VERSION 5.8 ;
BUSBITCHARS "[]" ;
DIVIDERCHAR "/" ;
UNITS
    DATABASE MICRONS 1000 ;
END UNITS

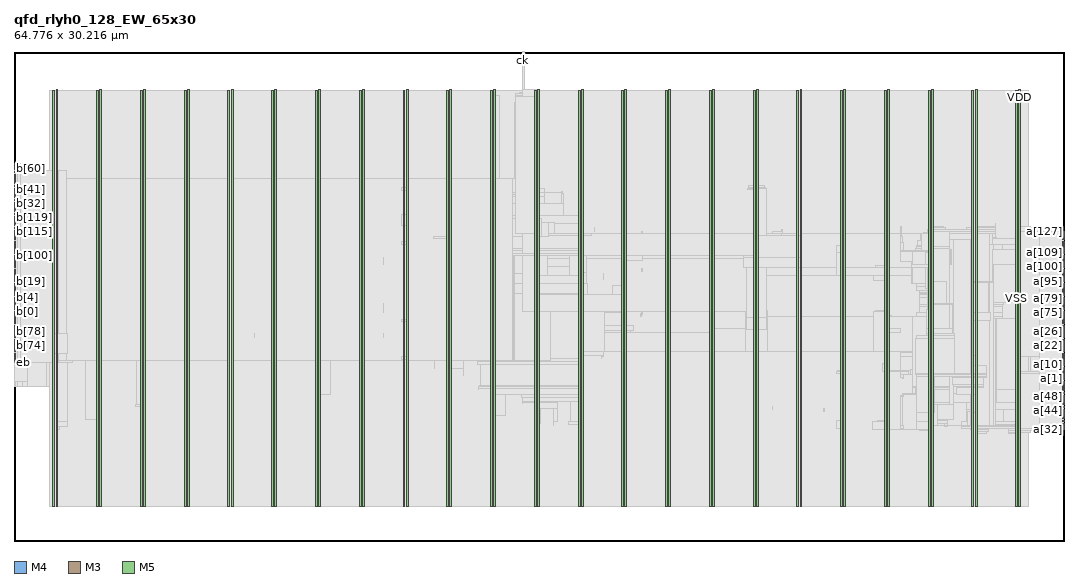
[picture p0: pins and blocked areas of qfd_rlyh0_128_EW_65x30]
MACRO qfd_rlyh0_128_EW_65x30
  FOREIGN qfd_rlyh0_128_EW_65x30 0 0 ;
  CLASS BLOCK ;
  SIZE 64.776 BY 30.216 ;
  PIN a[0]
    DIRECTION INPUT ;
    USE SIGNAL ;
    PORT
      LAYER M4 ;
        RECT  64.692 9.936 64.776 9.96 ;
    END
  END a[0]
  PIN a[100]
    DIRECTION INPUT ;
    USE SIGNAL ;
    PORT
      LAYER M4 ;
        RECT  64.692 16.464 64.776 16.488 ;
    END
  END a[100]
  PIN a[101]
    DIRECTION INPUT ;
    USE SIGNAL ;
    PORT
      LAYER M4 ;
        RECT  64.692 16.56 64.776 16.584 ;
    END
  END a[101]
  PIN a[102]
    DIRECTION INPUT ;
    USE SIGNAL ;
    PORT
      LAYER M4 ;
        RECT  64.692 16.656 64.776 16.68 ;
    END
  END a[102]
  PIN a[103]
    DIRECTION INPUT ;
    USE SIGNAL ;
    PORT
      LAYER M4 ;
        RECT  64.692 16.752 64.776 16.776 ;
    END
  END a[103]
  PIN a[104]
    DIRECTION INPUT ;
    USE SIGNAL ;
    PORT
      LAYER M4 ;
        RECT  64.692 16.848 64.776 16.872 ;
    END
  END a[104]
  PIN a[105]
    DIRECTION INPUT ;
    USE SIGNAL ;
    PORT
      LAYER M4 ;
        RECT  64.692 16.944 64.776 16.968 ;
    END
  END a[105]
  PIN a[106]
    DIRECTION INPUT ;
    USE SIGNAL ;
    PORT
      LAYER M4 ;
        RECT  64.692 17.04 64.776 17.064 ;
    END
  END a[106]
  PIN a[107]
    DIRECTION INPUT ;
    USE SIGNAL ;
    PORT
      LAYER M4 ;
        RECT  64.692 17.136 64.776 17.16 ;
    END
  END a[107]
  PIN a[108]
    DIRECTION INPUT ;
    USE SIGNAL ;
    PORT
      LAYER M4 ;
        RECT  64.692 17.232 64.776 17.256 ;
    END
  END a[108]
  PIN a[109]
    DIRECTION INPUT ;
    USE SIGNAL ;
    PORT
      LAYER M4 ;
        RECT  64.692 17.328 64.776 17.352 ;
    END
  END a[109]
  PIN a[10]
    DIRECTION INPUT ;
    USE SIGNAL ;
    PORT
      LAYER M4 ;
        RECT  64.692 10.896 64.776 10.92 ;
    END
  END a[10]
  PIN a[110]
    DIRECTION INPUT ;
    USE SIGNAL ;
    PORT
      LAYER M4 ;
        RECT  64.692 17.424 64.776 17.448 ;
    END
  END a[110]
  PIN a[111]
    DIRECTION INPUT ;
    USE SIGNAL ;
    PORT
      LAYER M4 ;
        RECT  64.692 17.52 64.776 17.544 ;
    END
  END a[111]
  PIN a[112]
    DIRECTION INPUT ;
    USE SIGNAL ;
    PORT
      LAYER M4 ;
        RECT  64.692 17.616 64.776 17.64 ;
    END
  END a[112]
  PIN a[113]
    DIRECTION INPUT ;
    USE SIGNAL ;
    PORT
      LAYER M4 ;
        RECT  64.692 17.712 64.776 17.736 ;
    END
  END a[113]
  PIN a[114]
    DIRECTION INPUT ;
    USE SIGNAL ;
    PORT
      LAYER M4 ;
        RECT  64.692 17.808 64.776 17.832 ;
    END
  END a[114]
  PIN a[115]
    DIRECTION INPUT ;
    USE SIGNAL ;
    PORT
      LAYER M4 ;
        RECT  64.692 17.904 64.776 17.928 ;
    END
  END a[115]
  PIN a[116]
    DIRECTION INPUT ;
    USE SIGNAL ;
    PORT
      LAYER M4 ;
        RECT  64.692 18 64.776 18.024 ;
    END
  END a[116]
  PIN a[117]
    DIRECTION INPUT ;
    USE SIGNAL ;
    PORT
      LAYER M4 ;
        RECT  64.692 18.096 64.776 18.12 ;
    END
  END a[117]
  PIN a[118]
    DIRECTION INPUT ;
    USE SIGNAL ;
    PORT
      LAYER M4 ;
        RECT  64.692 18.192 64.776 18.216 ;
    END
  END a[118]
  PIN a[119]
    DIRECTION INPUT ;
    USE SIGNAL ;
    PORT
      LAYER M4 ;
        RECT  64.692 18.288 64.776 18.312 ;
    END
  END a[119]
  PIN a[11]
    DIRECTION INPUT ;
    USE SIGNAL ;
    PORT
      LAYER M4 ;
        RECT  64.692 10.992 64.776 11.016 ;
    END
  END a[11]
  PIN a[120]
    DIRECTION INPUT ;
    USE SIGNAL ;
    PORT
      LAYER M4 ;
        RECT  64.692 18.384 64.776 18.408 ;
    END
  END a[120]
  PIN a[121]
    DIRECTION INPUT ;
    USE SIGNAL ;
    PORT
      LAYER M4 ;
        RECT  64.692 18.48 64.776 18.504 ;
    END
  END a[121]
  PIN a[122]
    DIRECTION INPUT ;
    USE SIGNAL ;
    PORT
      LAYER M4 ;
        RECT  64.692 18.576 64.776 18.6 ;
    END
  END a[122]
  PIN a[123]
    DIRECTION INPUT ;
    USE SIGNAL ;
    PORT
      LAYER M4 ;
        RECT  64.692 18.672 64.776 18.696 ;
    END
  END a[123]
  PIN a[124]
    DIRECTION INPUT ;
    USE SIGNAL ;
    PORT
      LAYER M4 ;
        RECT  64.692 18.768 64.776 18.792 ;
    END
  END a[124]
  PIN a[125]
    DIRECTION INPUT ;
    USE SIGNAL ;
    PORT
      LAYER M4 ;
        RECT  64.692 18.864 64.776 18.888 ;
    END
  END a[125]
  PIN a[126]
    DIRECTION INPUT ;
    USE SIGNAL ;
    PORT
      LAYER M4 ;
        RECT  64.692 18.96 64.776 18.984 ;
    END
  END a[126]
  PIN a[127]
    DIRECTION INPUT ;
    USE SIGNAL ;
    PORT
      LAYER M4 ;
        RECT  64.692 19.056 64.776 19.08 ;
    END
  END a[127]
  PIN a[12]
    DIRECTION INPUT ;
    USE SIGNAL ;
    PORT
      LAYER M4 ;
        RECT  64.692 11.088 64.776 11.112 ;
    END
  END a[12]
  PIN a[13]
    DIRECTION INPUT ;
    USE SIGNAL ;
    PORT
      LAYER M4 ;
        RECT  64.692 11.184 64.776 11.208 ;
    END
  END a[13]
  PIN a[14]
    DIRECTION INPUT ;
    USE SIGNAL ;
    PORT
      LAYER M4 ;
        RECT  64.692 11.28 64.776 11.304 ;
    END
  END a[14]
  PIN a[15]
    DIRECTION INPUT ;
    USE SIGNAL ;
    PORT
      LAYER M4 ;
        RECT  64.692 11.376 64.776 11.4 ;
    END
  END a[15]
  PIN a[16]
    DIRECTION INPUT ;
    USE SIGNAL ;
    PORT
      LAYER M4 ;
        RECT  64.692 11.472 64.776 11.496 ;
    END
  END a[16]
  PIN a[17]
    DIRECTION INPUT ;
    USE SIGNAL ;
    PORT
      LAYER M4 ;
        RECT  64.692 11.568 64.776 11.592 ;
    END
  END a[17]
  PIN a[18]
    DIRECTION INPUT ;
    USE SIGNAL ;
    PORT
      LAYER M4 ;
        RECT  64.692 11.664 64.776 11.688 ;
    END
  END a[18]
  PIN a[19]
    DIRECTION INPUT ;
    USE SIGNAL ;
    PORT
      LAYER M4 ;
        RECT  64.692 11.76 64.776 11.784 ;
    END
  END a[19]
  PIN a[1]
    DIRECTION INPUT ;
    USE SIGNAL ;
    PORT
      LAYER M4 ;
        RECT  64.692 10.032 64.776 10.056 ;
    END
  END a[1]
  PIN a[20]
    DIRECTION INPUT ;
    USE SIGNAL ;
    PORT
      LAYER M4 ;
        RECT  64.692 11.856 64.776 11.88 ;
    END
  END a[20]
  PIN a[21]
    DIRECTION INPUT ;
    USE SIGNAL ;
    PORT
      LAYER M4 ;
        RECT  64.692 11.952 64.776 11.976 ;
    END
  END a[21]
  PIN a[22]
    DIRECTION INPUT ;
    USE SIGNAL ;
    PORT
      LAYER M4 ;
        RECT  64.692 12.048 64.776 12.072 ;
    END
  END a[22]
  PIN a[23]
    DIRECTION INPUT ;
    USE SIGNAL ;
    PORT
      LAYER M4 ;
        RECT  64.692 12.144 64.776 12.168 ;
    END
  END a[23]
  PIN a[24]
    DIRECTION INPUT ;
    USE SIGNAL ;
    PORT
      LAYER M4 ;
        RECT  64.692 12.24 64.776 12.264 ;
    END
  END a[24]
  PIN a[25]
    DIRECTION INPUT ;
    USE SIGNAL ;
    PORT
      LAYER M4 ;
        RECT  64.692 12.336 64.776 12.36 ;
    END
  END a[25]
  PIN a[26]
    DIRECTION INPUT ;
    USE SIGNAL ;
    PORT
      LAYER M4 ;
        RECT  64.692 12.432 64.776 12.456 ;
    END
  END a[26]
  PIN a[27]
    DIRECTION INPUT ;
    USE SIGNAL ;
    PORT
      LAYER M4 ;
        RECT  64.692 12.528 64.776 12.552 ;
    END
  END a[27]
  PIN a[28]
    DIRECTION INPUT ;
    USE SIGNAL ;
    PORT
      LAYER M4 ;
        RECT  64.692 12.624 64.776 12.648 ;
    END
  END a[28]
  PIN a[29]
    DIRECTION INPUT ;
    USE SIGNAL ;
    PORT
      LAYER M4 ;
        RECT  64.692 12.72 64.776 12.744 ;
    END
  END a[29]
  PIN a[2]
    DIRECTION INPUT ;
    USE SIGNAL ;
    PORT
      LAYER M4 ;
        RECT  64.692 10.128 64.776 10.152 ;
    END
  END a[2]
  PIN a[30]
    DIRECTION INPUT ;
    USE SIGNAL ;
    PORT
      LAYER M4 ;
        RECT  64.692 12.816 64.776 12.84 ;
    END
  END a[30]
  PIN a[31]
    DIRECTION INPUT ;
    USE SIGNAL ;
    PORT
      LAYER M4 ;
        RECT  64.692 12.912 64.776 12.936 ;
    END
  END a[31]
  PIN a[32]
    DIRECTION INPUT ;
    USE SIGNAL ;
    PORT
      LAYER M4 ;
        RECT  64.692 6.864 64.776 6.888 ;
    END
  END a[32]
  PIN a[33]
    DIRECTION INPUT ;
    USE SIGNAL ;
    PORT
      LAYER M4 ;
        RECT  64.692 6.96 64.776 6.984 ;
    END
  END a[33]
  PIN a[34]
    DIRECTION INPUT ;
    USE SIGNAL ;
    PORT
      LAYER M4 ;
        RECT  64.692 7.056 64.776 7.08 ;
    END
  END a[34]
  PIN a[35]
    DIRECTION INPUT ;
    USE SIGNAL ;
    PORT
      LAYER M4 ;
        RECT  64.692 7.152 64.776 7.176 ;
    END
  END a[35]
  PIN a[36]
    DIRECTION INPUT ;
    USE SIGNAL ;
    PORT
      LAYER M4 ;
        RECT  64.692 7.248 64.776 7.272 ;
    END
  END a[36]
  PIN a[37]
    DIRECTION INPUT ;
    USE SIGNAL ;
    PORT
      LAYER M4 ;
        RECT  64.692 7.344 64.776 7.368 ;
    END
  END a[37]
  PIN a[38]
    DIRECTION INPUT ;
    USE SIGNAL ;
    PORT
      LAYER M4 ;
        RECT  64.692 7.44 64.776 7.464 ;
    END
  END a[38]
  PIN a[39]
    DIRECTION INPUT ;
    USE SIGNAL ;
    PORT
      LAYER M4 ;
        RECT  64.692 7.536 64.776 7.56 ;
    END
  END a[39]
  PIN a[3]
    DIRECTION INPUT ;
    USE SIGNAL ;
    PORT
      LAYER M4 ;
        RECT  64.692 10.224 64.776 10.248 ;
    END
  END a[3]
  PIN a[40]
    DIRECTION INPUT ;
    USE SIGNAL ;
    PORT
      LAYER M4 ;
        RECT  64.692 7.632 64.776 7.656 ;
    END
  END a[40]
  PIN a[41]
    DIRECTION INPUT ;
    USE SIGNAL ;
    PORT
      LAYER M4 ;
        RECT  64.692 7.728 64.776 7.752 ;
    END
  END a[41]
  PIN a[42]
    DIRECTION INPUT ;
    USE SIGNAL ;
    PORT
      LAYER M4 ;
        RECT  64.692 7.824 64.776 7.848 ;
    END
  END a[42]
  PIN a[43]
    DIRECTION INPUT ;
    USE SIGNAL ;
    PORT
      LAYER M4 ;
        RECT  64.692 7.92 64.776 7.944 ;
    END
  END a[43]
  PIN a[44]
    DIRECTION INPUT ;
    USE SIGNAL ;
    PORT
      LAYER M4 ;
        RECT  64.692 8.016 64.776 8.04 ;
    END
  END a[44]
  PIN a[45]
    DIRECTION INPUT ;
    USE SIGNAL ;
    PORT
      LAYER M4 ;
        RECT  64.692 8.112 64.776 8.136 ;
    END
  END a[45]
  PIN a[46]
    DIRECTION INPUT ;
    USE SIGNAL ;
    PORT
      LAYER M4 ;
        RECT  64.692 8.208 64.776 8.232 ;
    END
  END a[46]
  PIN a[47]
    DIRECTION INPUT ;
    USE SIGNAL ;
    PORT
      LAYER M4 ;
        RECT  64.692 8.304 64.776 8.328 ;
    END
  END a[47]
  PIN a[48]
    DIRECTION INPUT ;
    USE SIGNAL ;
    PORT
      LAYER M4 ;
        RECT  64.692 8.4 64.776 8.424 ;
    END
  END a[48]
  PIN a[49]
    DIRECTION INPUT ;
    USE SIGNAL ;
    PORT
      LAYER M4 ;
        RECT  64.692 8.496 64.776 8.52 ;
    END
  END a[49]
  PIN a[4]
    DIRECTION INPUT ;
    USE SIGNAL ;
    PORT
      LAYER M4 ;
        RECT  64.692 10.32 64.776 10.344 ;
    END
  END a[4]
  PIN a[50]
    DIRECTION INPUT ;
    USE SIGNAL ;
    PORT
      LAYER M4 ;
        RECT  64.692 8.592 64.776 8.616 ;
    END
  END a[50]
  PIN a[51]
    DIRECTION INPUT ;
    USE SIGNAL ;
    PORT
      LAYER M4 ;
        RECT  64.692 8.688 64.776 8.712 ;
    END
  END a[51]
  PIN a[52]
    DIRECTION INPUT ;
    USE SIGNAL ;
    PORT
      LAYER M4 ;
        RECT  64.692 8.784 64.776 8.808 ;
    END
  END a[52]
  PIN a[53]
    DIRECTION INPUT ;
    USE SIGNAL ;
    PORT
      LAYER M4 ;
        RECT  64.692 8.88 64.776 8.904 ;
    END
  END a[53]
  PIN a[54]
    DIRECTION INPUT ;
    USE SIGNAL ;
    PORT
      LAYER M4 ;
        RECT  64.692 8.976 64.776 9 ;
    END
  END a[54]
  PIN a[55]
    DIRECTION INPUT ;
    USE SIGNAL ;
    PORT
      LAYER M4 ;
        RECT  64.692 9.072 64.776 9.096 ;
    END
  END a[55]
  PIN a[56]
    DIRECTION INPUT ;
    USE SIGNAL ;
    PORT
      LAYER M4 ;
        RECT  64.692 9.168 64.776 9.192 ;
    END
  END a[56]
  PIN a[57]
    DIRECTION INPUT ;
    USE SIGNAL ;
    PORT
      LAYER M4 ;
        RECT  64.692 9.264 64.776 9.288 ;
    END
  END a[57]
  PIN a[58]
    DIRECTION INPUT ;
    USE SIGNAL ;
    PORT
      LAYER M4 ;
        RECT  64.692 9.36 64.776 9.384 ;
    END
  END a[58]
  PIN a[59]
    DIRECTION INPUT ;
    USE SIGNAL ;
    PORT
      LAYER M4 ;
        RECT  64.692 9.456 64.776 9.48 ;
    END
  END a[59]
  PIN a[5]
    DIRECTION INPUT ;
    USE SIGNAL ;
    PORT
      LAYER M4 ;
        RECT  64.692 10.416 64.776 10.44 ;
    END
  END a[5]
  PIN a[60]
    DIRECTION INPUT ;
    USE SIGNAL ;
    PORT
      LAYER M4 ;
        RECT  64.692 9.552 64.776 9.576 ;
    END
  END a[60]
  PIN a[61]
    DIRECTION INPUT ;
    USE SIGNAL ;
    PORT
      LAYER M4 ;
        RECT  64.692 9.648 64.776 9.672 ;
    END
  END a[61]
  PIN a[62]
    DIRECTION INPUT ;
    USE SIGNAL ;
    PORT
      LAYER M4 ;
        RECT  64.692 9.744 64.776 9.768 ;
    END
  END a[62]
  PIN a[63]
    DIRECTION INPUT ;
    USE SIGNAL ;
    PORT
      LAYER M4 ;
        RECT  64.692 9.84 64.776 9.864 ;
    END
  END a[63]
  PIN a[64]
    DIRECTION INPUT ;
    USE SIGNAL ;
    PORT
      LAYER M4 ;
        RECT  64.692 13.008 64.776 13.032 ;
    END
  END a[64]
  PIN a[65]
    DIRECTION INPUT ;
    USE SIGNAL ;
    PORT
      LAYER M4 ;
        RECT  64.692 13.104 64.776 13.128 ;
    END
  END a[65]
  PIN a[66]
    DIRECTION INPUT ;
    USE SIGNAL ;
    PORT
      LAYER M4 ;
        RECT  64.692 13.2 64.776 13.224 ;
    END
  END a[66]
  PIN a[67]
    DIRECTION INPUT ;
    USE SIGNAL ;
    PORT
      LAYER M4 ;
        RECT  64.692 13.296 64.776 13.32 ;
    END
  END a[67]
  PIN a[68]
    DIRECTION INPUT ;
    USE SIGNAL ;
    PORT
      LAYER M4 ;
        RECT  64.692 13.392 64.776 13.416 ;
    END
  END a[68]
  PIN a[69]
    DIRECTION INPUT ;
    USE SIGNAL ;
    PORT
      LAYER M4 ;
        RECT  64.692 13.488 64.776 13.512 ;
    END
  END a[69]
  PIN a[6]
    DIRECTION INPUT ;
    USE SIGNAL ;
    PORT
      LAYER M4 ;
        RECT  64.692 10.512 64.776 10.536 ;
    END
  END a[6]
  PIN a[70]
    DIRECTION INPUT ;
    USE SIGNAL ;
    PORT
      LAYER M4 ;
        RECT  64.692 13.584 64.776 13.608 ;
    END
  END a[70]
  PIN a[71]
    DIRECTION INPUT ;
    USE SIGNAL ;
    PORT
      LAYER M4 ;
        RECT  64.692 13.68 64.776 13.704 ;
    END
  END a[71]
  PIN a[72]
    DIRECTION INPUT ;
    USE SIGNAL ;
    PORT
      LAYER M4 ;
        RECT  64.692 13.776 64.776 13.8 ;
    END
  END a[72]
  PIN a[73]
    DIRECTION INPUT ;
    USE SIGNAL ;
    PORT
      LAYER M4 ;
        RECT  64.692 13.872 64.776 13.896 ;
    END
  END a[73]
  PIN a[74]
    DIRECTION INPUT ;
    USE SIGNAL ;
    PORT
      LAYER M4 ;
        RECT  64.692 13.968 64.776 13.992 ;
    END
  END a[74]
  PIN a[75]
    DIRECTION INPUT ;
    USE SIGNAL ;
    PORT
      LAYER M4 ;
        RECT  64.692 14.064 64.776 14.088 ;
    END
  END a[75]
  PIN a[76]
    DIRECTION INPUT ;
    USE SIGNAL ;
    PORT
      LAYER M4 ;
        RECT  64.692 14.16 64.776 14.184 ;
    END
  END a[76]
  PIN a[77]
    DIRECTION INPUT ;
    USE SIGNAL ;
    PORT
      LAYER M4 ;
        RECT  64.692 14.256 64.776 14.28 ;
    END
  END a[77]
  PIN a[78]
    DIRECTION INPUT ;
    USE SIGNAL ;
    PORT
      LAYER M4 ;
        RECT  64.692 14.352 64.776 14.376 ;
    END
  END a[78]
  PIN a[79]
    DIRECTION INPUT ;
    USE SIGNAL ;
    PORT
      LAYER M4 ;
        RECT  64.692 14.448 64.776 14.472 ;
    END
  END a[79]
  PIN a[7]
    DIRECTION INPUT ;
    USE SIGNAL ;
    PORT
      LAYER M4 ;
        RECT  64.692 10.608 64.776 10.632 ;
    END
  END a[7]
  PIN a[80]
    DIRECTION INPUT ;
    USE SIGNAL ;
    PORT
      LAYER M4 ;
        RECT  64.692 14.544 64.776 14.568 ;
    END
  END a[80]
  PIN a[81]
    DIRECTION INPUT ;
    USE SIGNAL ;
    PORT
      LAYER M4 ;
        RECT  64.692 14.64 64.776 14.664 ;
    END
  END a[81]
  PIN a[82]
    DIRECTION INPUT ;
    USE SIGNAL ;
    PORT
      LAYER M4 ;
        RECT  64.692 14.736 64.776 14.76 ;
    END
  END a[82]
  PIN a[83]
    DIRECTION INPUT ;
    USE SIGNAL ;
    PORT
      LAYER M4 ;
        RECT  64.692 14.832 64.776 14.856 ;
    END
  END a[83]
  PIN a[84]
    DIRECTION INPUT ;
    USE SIGNAL ;
    PORT
      LAYER M4 ;
        RECT  64.692 14.928 64.776 14.952 ;
    END
  END a[84]
  PIN a[85]
    DIRECTION INPUT ;
    USE SIGNAL ;
    PORT
      LAYER M4 ;
        RECT  64.692 15.024 64.776 15.048 ;
    END
  END a[85]
  PIN a[86]
    DIRECTION INPUT ;
    USE SIGNAL ;
    PORT
      LAYER M4 ;
        RECT  64.692 15.12 64.776 15.144 ;
    END
  END a[86]
  PIN a[87]
    DIRECTION INPUT ;
    USE SIGNAL ;
    PORT
      LAYER M4 ;
        RECT  64.692 15.216 64.776 15.24 ;
    END
  END a[87]
  PIN a[88]
    DIRECTION INPUT ;
    USE SIGNAL ;
    PORT
      LAYER M4 ;
        RECT  64.692 15.312 64.776 15.336 ;
    END
  END a[88]
  PIN a[89]
    DIRECTION INPUT ;
    USE SIGNAL ;
    PORT
      LAYER M4 ;
        RECT  64.692 15.408 64.776 15.432 ;
    END
  END a[89]
  PIN a[8]
    DIRECTION INPUT ;
    USE SIGNAL ;
    PORT
      LAYER M4 ;
        RECT  64.692 10.704 64.776 10.728 ;
    END
  END a[8]
  PIN a[90]
    DIRECTION INPUT ;
    USE SIGNAL ;
    PORT
      LAYER M4 ;
        RECT  64.692 15.504 64.776 15.528 ;
    END
  END a[90]
  PIN a[91]
    DIRECTION INPUT ;
    USE SIGNAL ;
    PORT
      LAYER M4 ;
        RECT  64.692 15.6 64.776 15.624 ;
    END
  END a[91]
  PIN a[92]
    DIRECTION INPUT ;
    USE SIGNAL ;
    PORT
      LAYER M4 ;
        RECT  64.692 15.696 64.776 15.72 ;
    END
  END a[92]
  PIN a[93]
    DIRECTION INPUT ;
    USE SIGNAL ;
    PORT
      LAYER M4 ;
        RECT  64.692 15.792 64.776 15.816 ;
    END
  END a[93]
  PIN a[94]
    DIRECTION INPUT ;
    USE SIGNAL ;
    PORT
      LAYER M4 ;
        RECT  64.692 15.888 64.776 15.912 ;
    END
  END a[94]
  PIN a[95]
    DIRECTION INPUT ;
    USE SIGNAL ;
    PORT
      LAYER M4 ;
        RECT  64.692 15.984 64.776 16.008 ;
    END
  END a[95]
  PIN a[96]
    DIRECTION INPUT ;
    USE SIGNAL ;
    PORT
      LAYER M4 ;
        RECT  64.692 16.08 64.776 16.104 ;
    END
  END a[96]
  PIN a[97]
    DIRECTION INPUT ;
    USE SIGNAL ;
    PORT
      LAYER M4 ;
        RECT  64.692 16.176 64.776 16.2 ;
    END
  END a[97]
  PIN a[98]
    DIRECTION INPUT ;
    USE SIGNAL ;
    PORT
      LAYER M4 ;
        RECT  64.692 16.272 64.776 16.296 ;
    END
  END a[98]
  PIN a[99]
    DIRECTION INPUT ;
    USE SIGNAL ;
    PORT
      LAYER M4 ;
        RECT  64.692 16.368 64.776 16.392 ;
    END
  END a[99]
  PIN a[9]
    DIRECTION INPUT ;
    USE SIGNAL ;
    PORT
      LAYER M4 ;
        RECT  64.692 10.8 64.776 10.824 ;
    END
  END a[9]
  PIN b[0]
    DIRECTION OUTPUT ;
    USE SIGNAL ;
    PORT
      LAYER M4 ;
        RECT  0 14.16 0.084 14.184 ;
    END
  END b[0]
  PIN b[100]
    DIRECTION OUTPUT ;
    USE SIGNAL ;
    PORT
      LAYER M4 ;
        RECT  0 17.616 0.084 17.64 ;
    END
  END b[100]
  PIN b[101]
    DIRECTION OUTPUT ;
    USE SIGNAL ;
    PORT
      LAYER M4 ;
        RECT  0 17.712 0.084 17.736 ;
    END
  END b[101]
  PIN b[102]
    DIRECTION OUTPUT ;
    USE SIGNAL ;
    PORT
      LAYER M4 ;
        RECT  0 17.808 0.084 17.832 ;
    END
  END b[102]
  PIN b[103]
    DIRECTION OUTPUT ;
    USE SIGNAL ;
    PORT
      LAYER M4 ;
        RECT  0 17.904 0.084 17.928 ;
    END
  END b[103]
  PIN b[104]
    DIRECTION OUTPUT ;
    USE SIGNAL ;
    PORT
      LAYER M4 ;
        RECT  0 18 0.084 18.024 ;
    END
  END b[104]
  PIN b[105]
    DIRECTION OUTPUT ;
    USE SIGNAL ;
    PORT
      LAYER M4 ;
        RECT  0 18.096 0.084 18.12 ;
    END
  END b[105]
  PIN b[106]
    DIRECTION OUTPUT ;
    USE SIGNAL ;
    PORT
      LAYER M4 ;
        RECT  0 18.192 0.084 18.216 ;
    END
  END b[106]
  PIN b[107]
    DIRECTION OUTPUT ;
    USE SIGNAL ;
    PORT
      LAYER M4 ;
        RECT  0 18.288 0.084 18.312 ;
    END
  END b[107]
  PIN b[108]
    DIRECTION OUTPUT ;
    USE SIGNAL ;
    PORT
      LAYER M4 ;
        RECT  0 18.384 0.084 18.408 ;
    END
  END b[108]
  PIN b[109]
    DIRECTION OUTPUT ;
    USE SIGNAL ;
    PORT
      LAYER M4 ;
        RECT  0 18.48 0.084 18.504 ;
    END
  END b[109]
  PIN b[10]
    DIRECTION OUTPUT ;
    USE SIGNAL ;
    PORT
      LAYER M4 ;
        RECT  0 15.12 0.084 15.144 ;
    END
  END b[10]
  PIN b[110]
    DIRECTION OUTPUT ;
    USE SIGNAL ;
    PORT
      LAYER M4 ;
        RECT  0 18.576 0.084 18.6 ;
    END
  END b[110]
  PIN b[111]
    DIRECTION OUTPUT ;
    USE SIGNAL ;
    PORT
      LAYER M4 ;
        RECT  0 18.672 0.084 18.696 ;
    END
  END b[111]
  PIN b[112]
    DIRECTION OUTPUT ;
    USE SIGNAL ;
    PORT
      LAYER M4 ;
        RECT  0 18.768 0.084 18.792 ;
    END
  END b[112]
  PIN b[113]
    DIRECTION OUTPUT ;
    USE SIGNAL ;
    PORT
      LAYER M4 ;
        RECT  0 18.864 0.084 18.888 ;
    END
  END b[113]
  PIN b[114]
    DIRECTION OUTPUT ;
    USE SIGNAL ;
    PORT
      LAYER M4 ;
        RECT  0 18.96 0.084 18.984 ;
    END
  END b[114]
  PIN b[115]
    DIRECTION OUTPUT ;
    USE SIGNAL ;
    PORT
      LAYER M4 ;
        RECT  0 19.056 0.084 19.08 ;
    END
  END b[115]
  PIN b[116]
    DIRECTION OUTPUT ;
    USE SIGNAL ;
    PORT
      LAYER M4 ;
        RECT  0 19.152 0.084 19.176 ;
    END
  END b[116]
  PIN b[117]
    DIRECTION OUTPUT ;
    USE SIGNAL ;
    PORT
      LAYER M4 ;
        RECT  0 19.248 0.084 19.272 ;
    END
  END b[117]
  PIN b[118]
    DIRECTION OUTPUT ;
    USE SIGNAL ;
    PORT
      LAYER M4 ;
        RECT  0 19.344 0.084 19.368 ;
    END
  END b[118]
  PIN b[119]
    DIRECTION OUTPUT ;
    USE SIGNAL ;
    PORT
      LAYER M4 ;
        RECT  0 19.44 0.084 19.464 ;
    END
  END b[119]
  PIN b[11]
    DIRECTION OUTPUT ;
    USE SIGNAL ;
    PORT
      LAYER M4 ;
        RECT  0 15.216 0.084 15.24 ;
    END
  END b[11]
  PIN b[120]
    DIRECTION OUTPUT ;
    USE SIGNAL ;
    PORT
      LAYER M4 ;
        RECT  0 19.536 0.084 19.56 ;
    END
  END b[120]
  PIN b[121]
    DIRECTION OUTPUT ;
    USE SIGNAL ;
    PORT
      LAYER M4 ;
        RECT  0 19.632 0.084 19.656 ;
    END
  END b[121]
  PIN b[122]
    DIRECTION OUTPUT ;
    USE SIGNAL ;
    PORT
      LAYER M4 ;
        RECT  0 19.728 0.084 19.752 ;
    END
  END b[122]
  PIN b[123]
    DIRECTION OUTPUT ;
    USE SIGNAL ;
    PORT
      LAYER M4 ;
        RECT  0 19.824 0.084 19.848 ;
    END
  END b[123]
  PIN b[124]
    DIRECTION OUTPUT ;
    USE SIGNAL ;
    PORT
      LAYER M4 ;
        RECT  0 19.92 0.084 19.944 ;
    END
  END b[124]
  PIN b[125]
    DIRECTION OUTPUT ;
    USE SIGNAL ;
    PORT
      LAYER M4 ;
        RECT  0 20.016 0.084 20.04 ;
    END
  END b[125]
  PIN b[126]
    DIRECTION OUTPUT ;
    USE SIGNAL ;
    PORT
      LAYER M4 ;
        RECT  0 20.112 0.084 20.136 ;
    END
  END b[126]
  PIN b[127]
    DIRECTION OUTPUT ;
    USE SIGNAL ;
    PORT
      LAYER M4 ;
        RECT  0 20.208 0.084 20.232 ;
    END
  END b[127]
  PIN b[12]
    DIRECTION OUTPUT ;
    USE SIGNAL ;
    PORT
      LAYER M4 ;
        RECT  0 15.312 0.084 15.336 ;
    END
  END b[12]
  PIN b[13]
    DIRECTION OUTPUT ;
    USE SIGNAL ;
    PORT
      LAYER M4 ;
        RECT  0 15.408 0.084 15.432 ;
    END
  END b[13]
  PIN b[14]
    DIRECTION OUTPUT ;
    USE SIGNAL ;
    PORT
      LAYER M4 ;
        RECT  0 15.504 0.084 15.528 ;
    END
  END b[14]
  PIN b[15]
    DIRECTION OUTPUT ;
    USE SIGNAL ;
    PORT
      LAYER M4 ;
        RECT  0 15.6 0.084 15.624 ;
    END
  END b[15]
  PIN b[16]
    DIRECTION OUTPUT ;
    USE SIGNAL ;
    PORT
      LAYER M4 ;
        RECT  0 15.696 0.084 15.72 ;
    END
  END b[16]
  PIN b[17]
    DIRECTION OUTPUT ;
    USE SIGNAL ;
    PORT
      LAYER M4 ;
        RECT  0 15.792 0.084 15.816 ;
    END
  END b[17]
  PIN b[18]
    DIRECTION OUTPUT ;
    USE SIGNAL ;
    PORT
      LAYER M4 ;
        RECT  0 15.888 0.084 15.912 ;
    END
  END b[18]
  PIN b[19]
    DIRECTION OUTPUT ;
    USE SIGNAL ;
    PORT
      LAYER M4 ;
        RECT  0 15.984 0.084 16.008 ;
    END
  END b[19]
  PIN b[1]
    DIRECTION OUTPUT ;
    USE SIGNAL ;
    PORT
      LAYER M4 ;
        RECT  0 14.256 0.084 14.28 ;
    END
  END b[1]
  PIN b[20]
    DIRECTION OUTPUT ;
    USE SIGNAL ;
    PORT
      LAYER M4 ;
        RECT  0 16.08 0.084 16.104 ;
    END
  END b[20]
  PIN b[21]
    DIRECTION OUTPUT ;
    USE SIGNAL ;
    PORT
      LAYER M4 ;
        RECT  0 16.176 0.084 16.2 ;
    END
  END b[21]
  PIN b[22]
    DIRECTION OUTPUT ;
    USE SIGNAL ;
    PORT
      LAYER M4 ;
        RECT  0 16.272 0.084 16.296 ;
    END
  END b[22]
  PIN b[23]
    DIRECTION OUTPUT ;
    USE SIGNAL ;
    PORT
      LAYER M4 ;
        RECT  0 16.368 0.084 16.392 ;
    END
  END b[23]
  PIN b[24]
    DIRECTION OUTPUT ;
    USE SIGNAL ;
    PORT
      LAYER M4 ;
        RECT  0 16.464 0.084 16.488 ;
    END
  END b[24]
  PIN b[25]
    DIRECTION OUTPUT ;
    USE SIGNAL ;
    PORT
      LAYER M4 ;
        RECT  0 16.56 0.084 16.584 ;
    END
  END b[25]
  PIN b[26]
    DIRECTION OUTPUT ;
    USE SIGNAL ;
    PORT
      LAYER M4 ;
        RECT  0 16.656 0.084 16.68 ;
    END
  END b[26]
  PIN b[27]
    DIRECTION OUTPUT ;
    USE SIGNAL ;
    PORT
      LAYER M4 ;
        RECT  0 16.752 0.084 16.776 ;
    END
  END b[27]
  PIN b[28]
    DIRECTION OUTPUT ;
    USE SIGNAL ;
    PORT
      LAYER M4 ;
        RECT  0 16.848 0.084 16.872 ;
    END
  END b[28]
  PIN b[29]
    DIRECTION OUTPUT ;
    USE SIGNAL ;
    PORT
      LAYER M4 ;
        RECT  0 16.944 0.084 16.968 ;
    END
  END b[29]
  PIN b[2]
    DIRECTION OUTPUT ;
    USE SIGNAL ;
    PORT
      LAYER M4 ;
        RECT  0 14.352 0.084 14.376 ;
    END
  END b[2]
  PIN b[30]
    DIRECTION OUTPUT ;
    USE SIGNAL ;
    PORT
      LAYER M4 ;
        RECT  0 17.04 0.084 17.064 ;
    END
  END b[30]
  PIN b[31]
    DIRECTION OUTPUT ;
    USE SIGNAL ;
    PORT
      LAYER M4 ;
        RECT  0 17.136 0.084 17.16 ;
    END
  END b[31]
  PIN b[32]
    DIRECTION OUTPUT ;
    USE SIGNAL ;
    PORT
      LAYER M4 ;
        RECT  0 20.304 0.084 20.328 ;
    END
  END b[32]
  PIN b[33]
    DIRECTION OUTPUT ;
    USE SIGNAL ;
    PORT
      LAYER M4 ;
        RECT  0 20.4 0.084 20.424 ;
    END
  END b[33]
  PIN b[34]
    DIRECTION OUTPUT ;
    USE SIGNAL ;
    PORT
      LAYER M4 ;
        RECT  0 20.496 0.084 20.52 ;
    END
  END b[34]
  PIN b[35]
    DIRECTION OUTPUT ;
    USE SIGNAL ;
    PORT
      LAYER M4 ;
        RECT  0 20.592 0.084 20.616 ;
    END
  END b[35]
  PIN b[36]
    DIRECTION OUTPUT ;
    USE SIGNAL ;
    PORT
      LAYER M4 ;
        RECT  0 20.688 0.084 20.712 ;
    END
  END b[36]
  PIN b[37]
    DIRECTION OUTPUT ;
    USE SIGNAL ;
    PORT
      LAYER M4 ;
        RECT  0 20.784 0.084 20.808 ;
    END
  END b[37]
  PIN b[38]
    DIRECTION OUTPUT ;
    USE SIGNAL ;
    PORT
      LAYER M4 ;
        RECT  0 20.88 0.084 20.904 ;
    END
  END b[38]
  PIN b[39]
    DIRECTION OUTPUT ;
    USE SIGNAL ;
    PORT
      LAYER M4 ;
        RECT  0 20.976 0.084 21 ;
    END
  END b[39]
  PIN b[3]
    DIRECTION OUTPUT ;
    USE SIGNAL ;
    PORT
      LAYER M4 ;
        RECT  0 14.448 0.084 14.472 ;
    END
  END b[3]
  PIN b[40]
    DIRECTION OUTPUT ;
    USE SIGNAL ;
    PORT
      LAYER M4 ;
        RECT  0 21.072 0.084 21.096 ;
    END
  END b[40]
  PIN b[41]
    DIRECTION OUTPUT ;
    USE SIGNAL ;
    PORT
      LAYER M4 ;
        RECT  0 21.168 0.084 21.192 ;
    END
  END b[41]
  PIN b[42]
    DIRECTION OUTPUT ;
    USE SIGNAL ;
    PORT
      LAYER M4 ;
        RECT  0 21.264 0.084 21.288 ;
    END
  END b[42]
  PIN b[43]
    DIRECTION OUTPUT ;
    USE SIGNAL ;
    PORT
      LAYER M4 ;
        RECT  0 21.36 0.084 21.384 ;
    END
  END b[43]
  PIN b[44]
    DIRECTION OUTPUT ;
    USE SIGNAL ;
    PORT
      LAYER M4 ;
        RECT  0 21.456 0.084 21.48 ;
    END
  END b[44]
  PIN b[45]
    DIRECTION OUTPUT ;
    USE SIGNAL ;
    PORT
      LAYER M4 ;
        RECT  0 21.552 0.084 21.576 ;
    END
  END b[45]
  PIN b[46]
    DIRECTION OUTPUT ;
    USE SIGNAL ;
    PORT
      LAYER M4 ;
        RECT  0 21.648 0.084 21.672 ;
    END
  END b[46]
  PIN b[47]
    DIRECTION OUTPUT ;
    USE SIGNAL ;
    PORT
      LAYER M4 ;
        RECT  0 21.744 0.084 21.768 ;
    END
  END b[47]
  PIN b[48]
    DIRECTION OUTPUT ;
    USE SIGNAL ;
    PORT
      LAYER M4 ;
        RECT  0 21.84 0.084 21.864 ;
    END
  END b[48]
  PIN b[49]
    DIRECTION OUTPUT ;
    USE SIGNAL ;
    PORT
      LAYER M4 ;
        RECT  0 21.936 0.084 21.96 ;
    END
  END b[49]
  PIN b[4]
    DIRECTION OUTPUT ;
    USE SIGNAL ;
    PORT
      LAYER M4 ;
        RECT  0 14.544 0.084 14.568 ;
    END
  END b[4]
  PIN b[50]
    DIRECTION OUTPUT ;
    USE SIGNAL ;
    PORT
      LAYER M4 ;
        RECT  0 22.032 0.084 22.056 ;
    END
  END b[50]
  PIN b[51]
    DIRECTION OUTPUT ;
    USE SIGNAL ;
    PORT
      LAYER M4 ;
        RECT  0 22.128 0.084 22.152 ;
    END
  END b[51]
  PIN b[52]
    DIRECTION OUTPUT ;
    USE SIGNAL ;
    PORT
      LAYER M4 ;
        RECT  0 22.224 0.084 22.248 ;
    END
  END b[52]
  PIN b[53]
    DIRECTION OUTPUT ;
    USE SIGNAL ;
    PORT
      LAYER M4 ;
        RECT  0 22.32 0.084 22.344 ;
    END
  END b[53]
  PIN b[54]
    DIRECTION OUTPUT ;
    USE SIGNAL ;
    PORT
      LAYER M4 ;
        RECT  0 22.416 0.084 22.44 ;
    END
  END b[54]
  PIN b[55]
    DIRECTION OUTPUT ;
    USE SIGNAL ;
    PORT
      LAYER M4 ;
        RECT  0 22.512 0.084 22.536 ;
    END
  END b[55]
  PIN b[56]
    DIRECTION OUTPUT ;
    USE SIGNAL ;
    PORT
      LAYER M4 ;
        RECT  0 22.608 0.084 22.632 ;
    END
  END b[56]
  PIN b[57]
    DIRECTION OUTPUT ;
    USE SIGNAL ;
    PORT
      LAYER M4 ;
        RECT  0 22.704 0.084 22.728 ;
    END
  END b[57]
  PIN b[58]
    DIRECTION OUTPUT ;
    USE SIGNAL ;
    PORT
      LAYER M4 ;
        RECT  0 22.8 0.084 22.824 ;
    END
  END b[58]
  PIN b[59]
    DIRECTION OUTPUT ;
    USE SIGNAL ;
    PORT
      LAYER M4 ;
        RECT  0 22.896 0.084 22.92 ;
    END
  END b[59]
  PIN b[5]
    DIRECTION OUTPUT ;
    USE SIGNAL ;
    PORT
      LAYER M4 ;
        RECT  0 14.64 0.084 14.664 ;
    END
  END b[5]
  PIN b[60]
    DIRECTION OUTPUT ;
    USE SIGNAL ;
    PORT
      LAYER M4 ;
        RECT  0 22.992 0.084 23.016 ;
    END
  END b[60]
  PIN b[61]
    DIRECTION OUTPUT ;
    USE SIGNAL ;
    PORT
      LAYER M4 ;
        RECT  0 23.088 0.084 23.112 ;
    END
  END b[61]
  PIN b[62]
    DIRECTION OUTPUT ;
    USE SIGNAL ;
    PORT
      LAYER M4 ;
        RECT  0 23.184 0.084 23.208 ;
    END
  END b[62]
  PIN b[63]
    DIRECTION OUTPUT ;
    USE SIGNAL ;
    PORT
      LAYER M4 ;
        RECT  0 23.28 0.084 23.304 ;
    END
  END b[63]
  PIN b[64]
    DIRECTION OUTPUT ;
    USE SIGNAL ;
    PORT
      LAYER M4 ;
        RECT  0 11.088 0.084 11.112 ;
    END
  END b[64]
  PIN b[65]
    DIRECTION OUTPUT ;
    USE SIGNAL ;
    PORT
      LAYER M4 ;
        RECT  0 11.184 0.084 11.208 ;
    END
  END b[65]
  PIN b[66]
    DIRECTION OUTPUT ;
    USE SIGNAL ;
    PORT
      LAYER M4 ;
        RECT  0 11.28 0.084 11.304 ;
    END
  END b[66]
  PIN b[67]
    DIRECTION OUTPUT ;
    USE SIGNAL ;
    PORT
      LAYER M4 ;
        RECT  0 11.376 0.084 11.4 ;
    END
  END b[67]
  PIN b[68]
    DIRECTION OUTPUT ;
    USE SIGNAL ;
    PORT
      LAYER M4 ;
        RECT  0 11.472 0.084 11.496 ;
    END
  END b[68]
  PIN b[69]
    DIRECTION OUTPUT ;
    USE SIGNAL ;
    PORT
      LAYER M4 ;
        RECT  0 11.568 0.084 11.592 ;
    END
  END b[69]
  PIN b[6]
    DIRECTION OUTPUT ;
    USE SIGNAL ;
    PORT
      LAYER M4 ;
        RECT  0 14.736 0.084 14.76 ;
    END
  END b[6]
  PIN b[70]
    DIRECTION OUTPUT ;
    USE SIGNAL ;
    PORT
      LAYER M4 ;
        RECT  0 11.664 0.084 11.688 ;
    END
  END b[70]
  PIN b[71]
    DIRECTION OUTPUT ;
    USE SIGNAL ;
    PORT
      LAYER M4 ;
        RECT  0 11.76 0.084 11.784 ;
    END
  END b[71]
  PIN b[72]
    DIRECTION OUTPUT ;
    USE SIGNAL ;
    PORT
      LAYER M4 ;
        RECT  0 11.856 0.084 11.88 ;
    END
  END b[72]
  PIN b[73]
    DIRECTION OUTPUT ;
    USE SIGNAL ;
    PORT
      LAYER M4 ;
        RECT  0 11.952 0.084 11.976 ;
    END
  END b[73]
  PIN b[74]
    DIRECTION OUTPUT ;
    USE SIGNAL ;
    PORT
      LAYER M4 ;
        RECT  0 12.048 0.084 12.072 ;
    END
  END b[74]
  PIN b[75]
    DIRECTION OUTPUT ;
    USE SIGNAL ;
    PORT
      LAYER M4 ;
        RECT  0 12.144 0.084 12.168 ;
    END
  END b[75]
  PIN b[76]
    DIRECTION OUTPUT ;
    USE SIGNAL ;
    PORT
      LAYER M4 ;
        RECT  0 12.24 0.084 12.264 ;
    END
  END b[76]
  PIN b[77]
    DIRECTION OUTPUT ;
    USE SIGNAL ;
    PORT
      LAYER M4 ;
        RECT  0 12.336 0.084 12.36 ;
    END
  END b[77]
  PIN b[78]
    DIRECTION OUTPUT ;
    USE SIGNAL ;
    PORT
      LAYER M4 ;
        RECT  0 12.432 0.084 12.456 ;
    END
  END b[78]
  PIN b[79]
    DIRECTION OUTPUT ;
    USE SIGNAL ;
    PORT
      LAYER M4 ;
        RECT  0 12.528 0.084 12.552 ;
    END
  END b[79]
  PIN b[7]
    DIRECTION OUTPUT ;
    USE SIGNAL ;
    PORT
      LAYER M4 ;
        RECT  0 14.832 0.084 14.856 ;
    END
  END b[7]
  PIN b[80]
    DIRECTION OUTPUT ;
    USE SIGNAL ;
    PORT
      LAYER M4 ;
        RECT  0 12.624 0.084 12.648 ;
    END
  END b[80]
  PIN b[81]
    DIRECTION OUTPUT ;
    USE SIGNAL ;
    PORT
      LAYER M4 ;
        RECT  0 12.72 0.084 12.744 ;
    END
  END b[81]
  PIN b[82]
    DIRECTION OUTPUT ;
    USE SIGNAL ;
    PORT
      LAYER M4 ;
        RECT  0 12.816 0.084 12.84 ;
    END
  END b[82]
  PIN b[83]
    DIRECTION OUTPUT ;
    USE SIGNAL ;
    PORT
      LAYER M4 ;
        RECT  0 12.912 0.084 12.936 ;
    END
  END b[83]
  PIN b[84]
    DIRECTION OUTPUT ;
    USE SIGNAL ;
    PORT
      LAYER M4 ;
        RECT  0 13.008 0.084 13.032 ;
    END
  END b[84]
  PIN b[85]
    DIRECTION OUTPUT ;
    USE SIGNAL ;
    PORT
      LAYER M4 ;
        RECT  0 13.104 0.084 13.128 ;
    END
  END b[85]
  PIN b[86]
    DIRECTION OUTPUT ;
    USE SIGNAL ;
    PORT
      LAYER M4 ;
        RECT  0 13.2 0.084 13.224 ;
    END
  END b[86]
  PIN b[87]
    DIRECTION OUTPUT ;
    USE SIGNAL ;
    PORT
      LAYER M4 ;
        RECT  0 13.296 0.084 13.32 ;
    END
  END b[87]
  PIN b[88]
    DIRECTION OUTPUT ;
    USE SIGNAL ;
    PORT
      LAYER M4 ;
        RECT  0 13.392 0.084 13.416 ;
    END
  END b[88]
  PIN b[89]
    DIRECTION OUTPUT ;
    USE SIGNAL ;
    PORT
      LAYER M4 ;
        RECT  0 13.488 0.084 13.512 ;
    END
  END b[89]
  PIN b[8]
    DIRECTION OUTPUT ;
    USE SIGNAL ;
    PORT
      LAYER M4 ;
        RECT  0 14.928 0.084 14.952 ;
    END
  END b[8]
  PIN b[90]
    DIRECTION OUTPUT ;
    USE SIGNAL ;
    PORT
      LAYER M4 ;
        RECT  0 13.584 0.084 13.608 ;
    END
  END b[90]
  PIN b[91]
    DIRECTION OUTPUT ;
    USE SIGNAL ;
    PORT
      LAYER M4 ;
        RECT  0 13.68 0.084 13.704 ;
    END
  END b[91]
  PIN b[92]
    DIRECTION OUTPUT ;
    USE SIGNAL ;
    PORT
      LAYER M4 ;
        RECT  0 13.776 0.084 13.8 ;
    END
  END b[92]
  PIN b[93]
    DIRECTION OUTPUT ;
    USE SIGNAL ;
    PORT
      LAYER M4 ;
        RECT  0 13.872 0.084 13.896 ;
    END
  END b[93]
  PIN b[94]
    DIRECTION OUTPUT ;
    USE SIGNAL ;
    PORT
      LAYER M4 ;
        RECT  0 13.968 0.084 13.992 ;
    END
  END b[94]
  PIN b[95]
    DIRECTION OUTPUT ;
    USE SIGNAL ;
    PORT
      LAYER M4 ;
        RECT  0 14.064 0.084 14.088 ;
    END
  END b[95]
  PIN b[96]
    DIRECTION OUTPUT ;
    USE SIGNAL ;
    PORT
      LAYER M4 ;
        RECT  0 17.232 0.084 17.256 ;
    END
  END b[96]
  PIN b[97]
    DIRECTION OUTPUT ;
    USE SIGNAL ;
    PORT
      LAYER M4 ;
        RECT  0 17.328 0.084 17.352 ;
    END
  END b[97]
  PIN b[98]
    DIRECTION OUTPUT ;
    USE SIGNAL ;
    PORT
      LAYER M4 ;
        RECT  0 17.424 0.084 17.448 ;
    END
  END b[98]
  PIN b[99]
    DIRECTION OUTPUT ;
    USE SIGNAL ;
    PORT
      LAYER M4 ;
        RECT  0 17.52 0.084 17.544 ;
    END
  END b[99]
  PIN b[9]
    DIRECTION OUTPUT ;
    USE SIGNAL ;
    PORT
      LAYER M4 ;
        RECT  0 15.024 0.084 15.048 ;
    END
  END b[9]
  PIN ck
    DIRECTION INPUT ;
    USE SIGNAL ;
    PORT
      LAYER M3 ;
        RECT  31.356 30.179 31.374 30.216 ;
    END
  END ck
  PIN ck_o
    DIRECTION OUTPUT ;
    USE SIGNAL ;
    PORT
      LAYER M3 ;
        RECT  31.428 30.179 31.446 30.216 ;
    END
  END ck_o
  PIN eb
    DIRECTION OUTPUT ;
    USE SIGNAL ;
    PORT
      LAYER M4 ;
        RECT  0 10.992 0.084 11.016 ;
    END
  END eb
  PIN en
    DIRECTION INPUT ;
    USE SIGNAL ;
    PORT
      LAYER M3 ;
        RECT  31.5 30.179 31.518 30.216 ;
    END
  END en
  PIN VDD
    DIRECTION INOUT ;
    USE POWER ;
    PORT
      LAYER M5 ;
        RECT  61.992 2.151 62.112 27.833 ;
        RECT  59.292 2.151 59.412 27.833 ;
        RECT  56.592 2.151 56.712 27.833 ;
        RECT  53.892 2.151 54.012 27.833 ;
        RECT  51.192 2.151 51.312 27.833 ;
        RECT  48.492 2.151 48.612 27.833 ;
        RECT  45.792 2.151 45.912 27.833 ;
        RECT  43.092 2.151 43.212 27.833 ;
        RECT  40.392 2.151 40.512 27.833 ;
        RECT  37.692 2.151 37.812 27.833 ;
        RECT  34.992 2.151 35.112 27.833 ;
        RECT  32.292 2.151 32.412 27.833 ;
        RECT  29.592 2.151 29.712 27.833 ;
        RECT  26.892 2.151 27.012 27.833 ;
        RECT  24.192 2.151 24.312 27.833 ;
        RECT  21.492 2.151 21.612 27.833 ;
        RECT  18.792 2.151 18.912 27.833 ;
        RECT  16.092 2.151 16.212 27.833 ;
        RECT  13.392 2.151 13.512 27.833 ;
        RECT  10.692 2.151 10.812 27.833 ;
        RECT  7.992 2.151 8.112 27.833 ;
        RECT  5.292 2.151 5.412 27.833 ;
        RECT  2.592 2.151 2.712 27.833 ;
    END
  END VDD
  PIN VSS
    DIRECTION INOUT ;
    USE GROUND ;
    PORT
      LAYER M5 ;
        RECT  61.8 2.137 61.92 27.819 ;
        RECT  59.1 2.137 59.22 27.819 ;
        RECT  56.4 2.137 56.52 27.819 ;
        RECT  53.7 2.137 53.82 27.819 ;
        RECT  51 2.137 51.12 27.819 ;
        RECT  48.3 2.137 48.42 27.819 ;
        RECT  45.6 2.137 45.72 27.819 ;
        RECT  42.9 2.137 43.02 27.819 ;
        RECT  40.2 2.137 40.32 27.819 ;
        RECT  37.5 2.137 37.62 27.819 ;
        RECT  34.8 2.137 34.92 27.819 ;
        RECT  32.1 2.137 32.22 27.819 ;
        RECT  29.4 2.137 29.52 27.819 ;
        RECT  26.7 2.137 26.82 27.819 ;
        RECT  24 2.137 24.12 27.819 ;
        RECT  21.3 2.137 21.42 27.819 ;
        RECT  18.6 2.137 18.72 27.819 ;
        RECT  15.9 2.137 16.02 27.819 ;
        RECT  13.2 2.137 13.32 27.819 ;
        RECT  10.5 2.137 10.62 27.819 ;
        RECT  7.8 2.137 7.92 27.819 ;
        RECT  5.1 2.137 5.22 27.819 ;
        RECT  2.4 2.137 2.52 27.819 ;
    END
  END VSS
  OBS
    LAYER RVTN ;
     RECT  2.16 2.16 62.586 2.295 ;
     RECT  2.16 2.565 62.586 2.835 ;
     RECT  2.16 3.105 62.586 3.375 ;
     RECT  2.16 3.645 62.586 3.915 ;
     RECT  2.16 4.185 62.586 4.455 ;
     RECT  2.16 4.725 62.586 4.995 ;
     RECT  2.16 5.265 62.586 5.535 ;
     RECT  2.16 5.805 62.586 6.075 ;
     RECT  2.16 6.345 62.586 6.615 ;
     RECT  2.16 6.885 62.586 7.155 ;
     RECT  2.16 7.425 62.586 7.695 ;
     RECT  2.16 7.965 62.586 8.235 ;
     RECT  2.16 8.505 62.586 8.775 ;
     RECT  2.16 9.045 62.586 9.315 ;
     RECT  2.16 9.585 62.586 9.855 ;
     RECT  2.16 10.125 62.586 10.395 ;
     RECT  2.16 10.665 62.586 10.935 ;
     RECT  2.16 11.205 62.586 11.475 ;
     RECT  2.16 11.745 62.586 12.015 ;
     RECT  2.16 12.285 62.586 12.555 ;
     RECT  2.16 12.825 62.586 13.095 ;
     RECT  2.16 13.365 62.586 13.635 ;
     RECT  2.16 13.905 62.586 14.175 ;
     RECT  2.16 14.445 62.586 14.715 ;
     RECT  2.16 14.985 62.586 15.255 ;
     RECT  2.16 15.525 62.586 15.795 ;
     RECT  2.16 16.065 62.586 16.335 ;
     RECT  2.16 16.605 62.586 16.875 ;
     RECT  2.16 17.145 62.586 17.415 ;
     RECT  2.16 17.685 62.586 17.955 ;
     RECT  2.16 18.225 62.586 18.495 ;
     RECT  2.16 18.765 62.586 19.035 ;
     RECT  2.16 19.305 62.586 19.575 ;
     RECT  2.16 19.845 62.586 20.115 ;
     RECT  2.16 20.385 62.586 20.655 ;
     RECT  2.16 20.925 62.586 21.195 ;
     RECT  2.16 21.465 62.586 21.735 ;
     RECT  2.16 22.005 62.586 22.275 ;
     RECT  2.16 22.545 62.586 22.815 ;
     RECT  2.16 23.085 62.586 23.355 ;
     RECT  2.16 23.625 62.586 23.895 ;
     RECT  2.16 24.165 62.586 24.435 ;
     RECT  2.16 24.705 62.586 24.975 ;
     RECT  2.16 25.245 62.586 25.515 ;
     RECT  2.16 25.785 62.586 26.055 ;
     RECT  2.16 26.325 62.586 26.595 ;
     RECT  2.16 26.865 62.586 27.135 ;
     RECT  2.16 27.405 62.586 27.675 ;
    LAYER RVTP ;
     RECT  2.16 2.295 62.586 2.565 ;
     RECT  2.16 2.835 62.586 3.105 ;
     RECT  2.16 3.375 62.586 3.645 ;
     RECT  2.16 3.915 62.586 4.185 ;
     RECT  2.16 4.455 62.586 4.725 ;
     RECT  2.16 4.995 62.586 5.265 ;
     RECT  2.16 5.535 62.586 5.805 ;
     RECT  2.16 6.075 62.586 6.345 ;
     RECT  2.16 6.615 62.586 6.885 ;
     RECT  2.16 7.155 62.586 7.425 ;
     RECT  2.16 7.695 62.586 7.965 ;
     RECT  2.16 8.235 62.586 8.505 ;
     RECT  2.16 8.775 62.586 9.045 ;
     RECT  2.16 9.315 62.586 9.585 ;
     RECT  2.16 9.855 62.586 10.125 ;
     RECT  2.16 10.395 62.586 10.665 ;
     RECT  2.16 10.935 62.586 11.205 ;
     RECT  2.16 11.475 62.586 11.745 ;
     RECT  2.16 12.015 62.586 12.285 ;
     RECT  2.16 12.555 62.586 12.825 ;
     RECT  2.16 13.095 62.586 13.365 ;
     RECT  2.16 13.635 62.586 13.905 ;
     RECT  2.16 14.175 62.586 14.445 ;
     RECT  2.16 14.715 62.586 14.985 ;
     RECT  2.16 15.255 62.586 15.525 ;
     RECT  2.16 15.795 62.586 16.065 ;
     RECT  2.16 16.335 62.586 16.605 ;
     RECT  2.16 16.875 62.586 17.145 ;
     RECT  2.16 17.415 62.586 17.685 ;
     RECT  2.16 17.955 62.586 18.225 ;
     RECT  2.16 18.495 62.586 18.765 ;
     RECT  2.16 19.035 62.586 19.305 ;
     RECT  2.16 19.575 62.586 19.845 ;
     RECT  2.16 20.115 62.586 20.385 ;
     RECT  2.16 20.655 62.586 20.925 ;
     RECT  2.16 21.195 62.586 21.465 ;
     RECT  2.16 21.735 62.586 22.005 ;
     RECT  2.16 22.275 62.586 22.545 ;
     RECT  2.16 22.815 62.586 23.085 ;
     RECT  2.16 23.355 62.586 23.625 ;
     RECT  2.16 23.895 62.586 24.165 ;
     RECT  2.16 24.435 62.586 24.705 ;
     RECT  2.16 24.975 62.586 25.245 ;
     RECT  2.16 25.515 62.586 25.785 ;
     RECT  2.16 26.055 62.586 26.325 ;
     RECT  2.16 26.595 62.586 26.865 ;
     RECT  2.16 27.135 62.586 27.405 ;
     RECT  2.16 27.675 62.586 27.81 ;
    LAYER M1 ;
     RECT  2.16 2.151 62.586 27.819 ;
    LAYER M2 ;
     RECT  0.031 9.558 0.067 9.576 ;
     RECT  0.031 21.636 0.103 21.654 ;
     RECT  0.067 22.482 0.103 22.5 ;
     RECT  0.103 21.438 0.131 21.654 ;
     RECT  0.103 22.482 0.167 22.734 ;
     RECT  0.103 12.681 0.203 12.924 ;
     RECT  0.103 14.22 0.203 14.472 ;
     RECT  0.103 16.65 0.203 17.289 ;
     RECT  0.103 18.198 0.203 18.45 ;
     RECT  0.131 21.438 0.203 21.492 ;
     RECT  0.067 9.558 0.211 10.116 ;
     RECT  0.139 10.908 0.211 10.926 ;
     RECT  0.203 14.382 0.211 14.472 ;
     RECT  0.167 22.716 0.211 22.734 ;
     RECT  0.211 22.716 0.275 22.806 ;
     RECT  0.211 14.382 0.283 14.814 ;
     RECT  0.275 22.716 0.311 22.734 ;
     RECT  0.283 14.382 0.347 14.904 ;
     RECT  0.347 14.418 0.355 14.904 ;
     RECT  0.283 13.104 0.383 13.32 ;
     RECT  0.319 20.466 0.391 20.484 ;
     RECT  0.383 13.104 0.419 13.239 ;
     RECT  0.419 13.221 0.455 13.239 ;
     RECT  0.211 9.558 0.535 10.926 ;
     RECT  0.391 20.466 0.535 20.574 ;
     RECT  0.355 14.418 1.039 14.976 ;
     RECT  0.203 16.65 1.039 16.668 ;
     RECT  1.039 17.46 1.111 17.478 ;
     RECT  0.535 19.926 1.111 20.574 ;
     RECT  0.203 21.474 1.111 21.492 ;
     RECT  0.535 9.558 1.975 11.034 ;
     RECT  1.975 9.558 2.16 11.304 ;
     RECT  1.039 14.418 2.16 16.668 ;
     RECT  1.111 17.424 2.16 17.478 ;
     RECT  1.111 18.738 2.16 20.574 ;
     RECT  1.111 21.438 2.16 21.492 ;
     RECT  31.279 30.006 31.379 30.024 ;
     RECT  2.16 2.151 62.586 27.819 ;
     RECT  62.586 6.696 62.699 19.368 ;
     RECT  62.699 6.696 62.735 19.332 ;
     RECT  62.735 6.822 63.275 19.332 ;
     RECT  63.275 7.128 63.311 19.332 ;
     RECT  63.311 8.046 63.347 12.312 ;
     RECT  63.311 13.41 63.347 17.172 ;
     RECT  63.311 17.928 63.347 19.332 ;
     RECT  63.347 13.41 63.851 16.02 ;
     RECT  63.311 7.128 63.887 7.146 ;
     RECT  63.347 8.28 63.887 12.312 ;
     RECT  63.851 13.446 63.887 16.02 ;
     RECT  63.347 16.776 63.887 16.794 ;
     RECT  63.347 18.036 63.887 19.332 ;
     RECT  63.887 11.646 63.923 12.006 ;
     RECT  63.887 14.184 63.923 14.436 ;
     RECT  63.887 15.228 63.923 15.246 ;
     RECT  63.887 18.036 63.923 19.26 ;
     RECT  63.923 18.036 63.959 18.054 ;
     RECT  63.923 19.008 63.995 19.26 ;
     RECT  63.995 19.242 64.031 19.26 ;
    LAYER M3 ;
     RECT  2.415 2.143 2.505 2.413 ;
     RECT  5.115 2.143 5.205 2.413 ;
     RECT  7.815 2.143 7.905 2.413 ;
     RECT  10.515 2.143 10.605 2.413 ;
     RECT  13.215 2.143 13.305 2.413 ;
     RECT  15.915 2.143 16.005 2.413 ;
     RECT  18.615 2.143 18.705 2.413 ;
     RECT  21.315 2.143 21.405 2.413 ;
     RECT  24.015 2.143 24.105 2.413 ;
     RECT  26.715 2.143 26.805 2.413 ;
     RECT  29.415 2.143 29.505 2.413 ;
     RECT  32.115 2.143 32.205 2.413 ;
     RECT  34.815 2.143 34.905 2.413 ;
     RECT  37.515 2.143 37.605 2.413 ;
     RECT  40.215 2.143 40.305 2.413 ;
     RECT  42.915 2.143 43.005 2.413 ;
     RECT  45.615 2.143 45.705 2.413 ;
     RECT  48.315 2.143 48.405 2.413 ;
     RECT  51.015 2.143 51.105 2.413 ;
     RECT  53.715 2.143 53.805 2.413 ;
     RECT  56.415 2.143 56.505 2.413 ;
     RECT  59.115 2.143 59.205 2.413 ;
     RECT  61.815 2.143 61.905 2.413 ;
     RECT  61.815 2.413 62.097 6.619 ;
     RECT  59.115 2.413 59.397 6.655 ;
     RECT  61.344 6.619 62.097 6.691 ;
     RECT  59.115 6.655 59.994 6.781 ;
     RECT  56.415 2.413 56.697 6.817 ;
     RECT  61.344 6.691 62.73 6.817 ;
     RECT  53.715 2.413 53.997 6.853 ;
     RECT  59.115 6.781 60.102 6.853 ;
     RECT  2.415 2.413 2.697 6.889 ;
     RECT  54.72 6.859 54.738 6.889 ;
     RECT  55.872 6.817 56.697 6.893 ;
     RECT  54.72 6.889 54.81 6.925 ;
     RECT  59.004 6.853 60.102 6.925 ;
     RECT  61.344 6.817 63.27 6.925 ;
     RECT  51.015 2.413 51.297 6.961 ;
     RECT  54.72 6.925 54.846 6.961 ;
     RECT  58.716 6.925 63.27 6.961 ;
     RECT  58.464 6.961 63.27 7.051 ;
     RECT  2.415 6.889 2.79 7.087 ;
     RECT  54.72 6.961 54.882 7.151 ;
     RECT  58.464 7.051 63.882 7.151 ;
     RECT  34.815 2.413 35.097 7.159 ;
     RECT  32.115 2.413 32.397 7.231 ;
     RECT  56.412 6.893 56.697 7.231 ;
     RECT  57.42 7.087 57.582 7.231 ;
     RECT  34.2 7.159 35.097 7.349 ;
     RECT  52.992 6.853 53.997 7.349 ;
     RECT  58.464 7.151 63.306 7.349 ;
     RECT  2.415 7.087 3.294 7.357 ;
     RECT  58.752 7.349 63.306 7.385 ;
     RECT  33.264 7.123 33.282 7.393 ;
     RECT  50.724 6.961 51.297 7.421 ;
     RECT  53.28 7.349 53.997 7.421 ;
     RECT  56.412 7.231 57.618 7.421 ;
     RECT  32.115 7.231 32.454 7.429 ;
     RECT  56.415 7.421 57.618 7.465 ;
     RECT  5.115 2.413 5.397 7.501 ;
     RECT  29.415 2.413 29.697 7.771 ;
     RECT  61.815 7.385 63.306 8.011 ;
     RECT  58.752 7.385 61.038 8.131 ;
     RECT  61.815 8.011 63.882 8.131 ;
     RECT  49.968 8.005 49.986 8.159 ;
     RECT  32.115 7.429 32.49 8.203 ;
     RECT  33.264 7.393 33.534 8.203 ;
     RECT  46.764 8.131 46.782 8.267 ;
     RECT  7.815 2.413 8.097 8.311 ;
     RECT  7.488 8.311 8.097 8.429 ;
     RECT  31.356 8.509 31.374 8.545 ;
     RECT  32.115 8.203 33.534 8.545 ;
     RECT  56.415 7.465 57.978 8.545 ;
     RECT  58.752 8.131 63.882 8.545 ;
     RECT  31.356 8.545 33.534 8.581 ;
     RECT  34.344 7.349 35.097 8.581 ;
     RECT  31.356 8.581 35.097 8.851 ;
     RECT  54.72 7.151 54.81 8.941 ;
     RECT  54.72 8.941 54.882 8.969 ;
     RECT  18.615 2.413 18.897 9.013 ;
     RECT  29.415 7.771 30.294 9.049 ;
     RECT  31.284 8.851 35.097 9.049 ;
     RECT  54.792 8.969 54.882 9.049 ;
     RECT  54.792 9.049 55.602 9.077 ;
     RECT  54.864 9.077 55.602 9.113 ;
     RECT  56.415 8.545 63.882 9.319 ;
     RECT  28.656 9.319 28.674 9.391 ;
     RECT  29.415 9.049 35.097 9.391 ;
     RECT  55.44 9.113 55.602 9.481 ;
     RECT  56.376 9.319 63.882 9.481 ;
     RECT  28.656 9.391 35.097 9.509 ;
     RECT  55.44 9.481 63.882 9.545 ;
     RECT  28.728 9.509 35.097 9.581 ;
     RECT  0.036 9.553 0.054 9.859 ;
     RECT  0.828 9.589 0.846 9.859 ;
     RECT  54.792 10.021 54.846 10.057 ;
     RECT  54.72 10.057 54.846 10.267 ;
     RECT  55.584 9.545 63.882 10.267 ;
     RECT  51.015 7.421 51.297 10.327 ;
     RECT  50.724 10.327 51.297 10.427 ;
     RECT  54.72 10.267 63.882 10.427 ;
     RECT  53.715 7.421 53.997 10.471 ;
     RECT  50.796 10.427 51.297 10.499 ;
     RECT  26.715 2.413 26.997 10.669 ;
     RECT  27.72 10.201 27.738 10.669 ;
     RECT  24.015 2.413 24.297 10.741 ;
     RECT  28.764 9.581 35.097 10.903 ;
     RECT  53.604 10.471 53.997 10.931 ;
     RECT  2.415 7.357 3.33 11.011 ;
     RECT  28.62 10.903 35.097 11.101 ;
     RECT  25.92 10.669 25.938 11.209 ;
     RECT  26.715 10.669 27.738 11.209 ;
     RECT  7.56 8.429 8.097 11.227 ;
     RECT  2.415 11.011 3.582 11.245 ;
     RECT  4.428 7.501 5.397 11.245 ;
     RECT  25.92 11.209 27.738 11.245 ;
     RECT  10.515 2.413 10.797 11.272 ;
     RECT  13.215 2.413 13.497 11.272 ;
     RECT  15.915 2.413 16.197 11.272 ;
     RECT  21.315 2.413 21.597 11.272 ;
     RECT  24.015 10.741 24.354 11.272 ;
     RECT  2.304 11.245 5.397 11.281 ;
     RECT  10.404 11.272 10.797 11.309 ;
     RECT  15.804 11.272 16.197 11.309 ;
     RECT  23.904 11.272 24.354 11.309 ;
     RECT  25.92 11.245 27.882 11.371 ;
     RECT  28.62 11.101 35.154 11.371 ;
     RECT  36.216 11.245 36.234 11.371 ;
     RECT  54.72 10.427 62.097 11.371 ;
     RECT  63.288 10.427 63.882 11.371 ;
     RECT  25.92 11.371 35.154 11.399 ;
     RECT  6.84 11.227 8.097 11.405 ;
     RECT  14.832 11.227 14.85 11.405 ;
     RECT  36.216 11.371 36.306 11.407 ;
     RECT  13.104 11.272 13.497 11.408 ;
     RECT  21.204 11.272 21.597 11.408 ;
     RECT  27.864 11.399 35.154 11.435 ;
     RECT  28.764 11.435 35.154 11.443 ;
     RECT  36.216 11.407 36.378 11.443 ;
     RECT  1.98 11.281 5.397 11.543 ;
     RECT  54.72 11.371 63.882 11.641 ;
     RECT  51.015 10.499 51.297 11.749 ;
     RECT  24.015 11.309 24.354 11.785 ;
     RECT  38.772 11.707 38.79 11.837 ;
     RECT  46.764 11.707 46.782 11.837 ;
     RECT  1.98 11.543 3.438 12.047 ;
     RECT  28.764 11.443 36.378 12.055 ;
     RECT  28.764 12.055 36.774 12.091 ;
     RECT  37.515 2.413 37.797 12.091 ;
     RECT  54.72 11.641 63.918 12.119 ;
     RECT  63.864 12.119 63.918 12.173 ;
     RECT  4.428 11.543 5.397 12.181 ;
     RECT  21.315 11.408 21.597 12.187 ;
     RECT  22.824 11.659 22.842 12.187 ;
     RECT  53.715 10.931 53.997 12.217 ;
     RECT  28.764 12.091 37.797 12.253 ;
     RECT  14.832 12.187 14.85 12.317 ;
     RECT  21.315 12.187 21.69 12.317 ;
     RECT  38.808 12.217 38.826 12.317 ;
     RECT  63.864 12.173 63.882 12.317 ;
     RECT  22.824 12.187 22.878 12.325 ;
     RECT  25.92 11.399 26.997 12.361 ;
     RECT  27.864 11.435 27.918 12.361 ;
     RECT  22.824 12.325 22.95 12.365 ;
     RECT  22.824 12.365 22.914 12.389 ;
     RECT  25.92 12.361 27.918 12.475 ;
     RECT  25.668 12.475 27.918 12.523 ;
     RECT  28.764 12.253 38.034 12.523 ;
     RECT  7.56 11.405 8.097 12.571 ;
     RECT  15.915 11.309 16.197 12.619 ;
     RECT  4.428 12.181 5.49 12.659 ;
     RECT  15.915 12.619 16.29 12.659 ;
     RECT  53.604 12.217 53.997 12.721 ;
     RECT  10.515 11.309 10.797 12.757 ;
     RECT  45.615 2.413 45.897 12.757 ;
     RECT  44.1 12.721 44.118 12.763 ;
     RECT  52.992 12.721 53.997 12.763 ;
     RECT  54.72 12.119 62.838 12.763 ;
     RECT  6.84 12.571 8.097 12.797 ;
     RECT  10.515 12.757 10.818 12.797 ;
     RECT  22.896 12.389 22.914 12.797 ;
     RECT  45.216 12.757 45.897 12.797 ;
     RECT  52.236 12.757 52.254 12.859 ;
     RECT  52.992 12.763 62.838 12.859 ;
     RECT  52.236 12.859 62.838 12.901 ;
     RECT  13.215 11.408 13.497 12.991 ;
     RECT  25.668 12.523 38.034 12.991 ;
     RECT  44.1 12.763 44.154 13.019 ;
     RECT  14.94 12.763 14.958 13.037 ;
     RECT  44.1 13.019 44.118 13.085 ;
     RECT  52.236 12.901 63.306 13.085 ;
     RECT  24.015 11.785 24.39 13.099 ;
     RECT  53.028 13.085 63.306 13.133 ;
     RECT  25.668 12.991 38.214 13.289 ;
     RECT  53.028 13.133 62.73 13.433 ;
     RECT  50.724 11.749 51.297 13.469 ;
     RECT  6.948 12.797 8.097 13.531 ;
     RECT  20.52 13.003 20.538 13.531 ;
     RECT  21.315 12.317 21.597 13.531 ;
     RECT  55.296 13.433 62.73 13.595 ;
     RECT  55.332 13.595 62.73 13.631 ;
     RECT  45.615 12.797 45.897 13.771 ;
     RECT  45.216 13.771 45.897 13.801 ;
     RECT  63.828 13.195 63.882 13.805 ;
     RECT  55.332 13.631 60.966 13.853 ;
     RECT  61.815 13.631 62.73 13.909 ;
     RECT  53.028 13.433 54.162 13.937 ;
     RECT  23.328 13.099 24.39 13.963 ;
     RECT  63.864 13.805 63.882 13.963 ;
     RECT  38.664 13.873 38.682 13.981 ;
     RECT  13.104 12.991 13.497 14.009 ;
     RECT  20.52 13.531 21.597 14.009 ;
     RECT  22.896 13.963 24.39 14.009 ;
     RECT  38.664 13.981 38.754 14.009 ;
     RECT  45.216 13.801 46.35 14.093 ;
     RECT  20.52 14.009 20.538 14.099 ;
     RECT  25.668 13.289 37.797 14.099 ;
     RECT  38.736 14.009 38.754 14.099 ;
     RECT  55.692 13.853 60.966 14.099 ;
     RECT  10.515 12.797 10.797 14.107 ;
     RECT  45.288 14.093 46.35 14.107 ;
     RECT  45.288 14.107 46.422 14.189 ;
     RECT  53.028 13.937 53.997 14.189 ;
     RECT  24.015 14.009 24.39 14.215 ;
     RECT  25.668 14.099 27.918 14.215 ;
     RECT  6.84 13.531 8.097 14.237 ;
     RECT  10.515 14.107 10.818 14.237 ;
     RECT  45.615 14.189 46.422 14.237 ;
     RECT  53.136 14.189 53.997 14.243 ;
     RECT  4.428 12.659 5.397 14.341 ;
     RECT  14.832 13.531 14.85 14.347 ;
     RECT  21.315 14.009 21.597 14.347 ;
     RECT  24.015 14.215 27.918 14.369 ;
     RECT  4.428 14.341 5.49 14.381 ;
     RECT  25.704 14.369 27.918 14.429 ;
     RECT  21.315 14.347 21.69 14.443 ;
     RECT  14.832 14.347 14.958 14.477 ;
     RECT  61.815 13.909 62.766 14.483 ;
     RECT  55.872 14.099 60.966 14.485 ;
     RECT  25.704 14.429 26.997 14.549 ;
     RECT  55.872 14.485 61.002 14.611 ;
     RECT  21.315 14.443 21.798 14.669 ;
     RECT  27.864 14.429 27.918 14.669 ;
     RECT  63.864 13.963 63.918 14.731 ;
     RECT  27.864 14.669 27.882 14.765 ;
     RECT  4.428 14.381 5.397 14.791 ;
     RECT  24.015 14.369 24.39 15.005 ;
     RECT  55.872 14.611 61.074 15.019 ;
     RECT  61.815 14.483 62.73 15.019 ;
     RECT  22.896 14.009 22.914 15.089 ;
     RECT  13.215 14.009 13.497 15.151 ;
     RECT  7.56 14.237 8.097 15.163 ;
     RECT  55.872 15.019 62.73 15.211 ;
     RECT  26.496 14.549 26.997 15.215 ;
     RECT  28.764 14.099 37.797 15.215 ;
     RECT  0.036 9.859 0.846 15.223 ;
     RECT  63.828 14.731 63.918 15.251 ;
     RECT  0.036 15.223 1.062 15.259 ;
     RECT  55.872 15.211 62.766 15.259 ;
     RECT  63.828 15.251 63.882 15.259 ;
     RECT  55.872 15.259 63.882 15.323 ;
     RECT  25.704 14.549 25.722 15.331 ;
     RECT  26.604 15.215 26.997 15.457 ;
     RECT  55.872 15.323 62.118 15.457 ;
     RECT  21.315 14.669 21.597 15.592 ;
     RECT  4.356 14.791 5.397 15.629 ;
     RECT  13.104 15.151 13.497 15.629 ;
     RECT  21.204 15.592 21.597 15.629 ;
     RECT  25.668 15.331 25.722 15.629 ;
     RECT  26.604 15.457 27.522 15.719 ;
     RECT  55.656 15.457 62.118 15.719 ;
     RECT  36.936 15.215 37.797 15.755 ;
     RECT  6.84 15.163 8.097 15.773 ;
     RECT  25.668 15.629 25.686 15.821 ;
     RECT  28.764 15.215 35.37 15.863 ;
     RECT  55.656 15.719 60.354 15.871 ;
     RECT  26.604 15.719 26.997 15.899 ;
     RECT  55.404 15.871 60.354 15.917 ;
     RECT  53.715 14.243 53.997 16.069 ;
     RECT  61.2 15.719 62.118 16.171 ;
     RECT  63.252 15.323 63.882 16.171 ;
     RECT  21.315 15.629 21.597 16.363 ;
     RECT  5.115 15.629 5.397 16.501 ;
     RECT  36.36 16.141 36.378 16.529 ;
     RECT  51.015 13.469 51.297 16.537 ;
     RECT  55.476 15.917 60.354 16.537 ;
     RECT  46.764 16.363 46.782 16.541 ;
     RECT  55.476 16.537 60.39 16.645 ;
     RECT  61.2 16.171 63.882 16.645 ;
     RECT  55.476 16.645 63.882 16.771 ;
     RECT  38.736 16.609 38.754 16.799 ;
     RECT  53.028 16.069 53.997 16.799 ;
     RECT  55.368 16.771 63.882 16.799 ;
     RECT  48.315 2.413 48.597 16.891 ;
     RECT  28.764 15.863 35.334 16.943 ;
     RECT  28.764 16.943 35.097 16.951 ;
     RECT  21.315 16.363 21.69 16.973 ;
     RECT  22.824 15.595 22.842 16.973 ;
     RECT  5.115 16.501 5.49 16.979 ;
     RECT  53.172 16.799 53.997 16.979 ;
     RECT  47.916 16.891 48.597 17.069 ;
     RECT  55.368 16.799 63.342 17.069 ;
     RECT  7.56 15.773 8.097 17.083 ;
     RECT  10.515 14.237 10.797 17.083 ;
     RECT  26.715 15.899 26.997 17.149 ;
     RECT  55.368 17.069 55.458 17.221 ;
     RECT  4.356 15.629 4.374 17.311 ;
     RECT  5.115 16.979 5.397 17.311 ;
     RECT  13.215 15.629 13.497 17.311 ;
     RECT  21.315 16.973 21.597 17.311 ;
     RECT  47.988 17.069 48.597 17.339 ;
     RECT  4.356 17.311 5.397 17.357 ;
     RECT  13.104 17.311 13.497 17.357 ;
     RECT  14.832 14.477 14.85 17.357 ;
     RECT  21.204 17.311 21.597 17.357 ;
     RECT  6.84 17.083 8.097 17.453 ;
     RECT  10.515 17.083 10.818 17.453 ;
     RECT  22.896 17.323 22.914 17.453 ;
     RECT  38.772 17.323 38.79 17.453 ;
     RECT  26.604 17.149 26.997 17.491 ;
     RECT  28.512 16.951 35.097 17.761 ;
     RECT  50.724 16.537 51.297 17.795 ;
     RECT  56.232 17.069 63.342 17.803 ;
     RECT  0.036 15.259 1.134 17.837 ;
     RECT  54.72 17.221 55.458 17.851 ;
     RECT  56.232 17.803 63.882 17.851 ;
     RECT  28.008 17.761 35.097 17.915 ;
     RECT  54.72 17.851 63.882 17.915 ;
     RECT  26.172 17.491 26.997 17.933 ;
     RECT  28.116 17.915 35.097 18.023 ;
     RECT  24.015 15.005 24.297 18.031 ;
     RECT  55.584 17.915 63.882 18.031 ;
     RECT  55.584 18.031 63.954 18.059 ;
     RECT  55.656 18.059 63.954 18.149 ;
     RECT  57.6 18.149 59.634 18.185 ;
     RECT  50.76 17.795 51.297 18.221 ;
     RECT  55.656 18.149 56.754 18.221 ;
     RECT  60.372 18.149 63.954 18.221 ;
     RECT  4.356 17.357 4.374 18.283 ;
     RECT  5.115 17.357 5.397 18.283 ;
     RECT  7.56 17.453 8.097 18.283 ;
     RECT  13.215 17.357 13.497 18.283 ;
     RECT  21.315 17.357 21.597 18.283 ;
     RECT  60.372 18.221 62.694 18.317 ;
     RECT  4.356 18.283 5.397 18.329 ;
     RECT  13.104 18.283 13.497 18.329 ;
     RECT  21.204 18.283 21.597 18.329 ;
     RECT  54.72 17.915 54.846 18.419 ;
     RECT  18.615 9.013 19.53 18.427 ;
     RECT  21.315 18.329 21.597 18.427 ;
     RECT  6.84 18.283 8.097 18.461 ;
     RECT  25.74 17.995 25.794 18.461 ;
     RECT  18.576 18.427 19.53 18.464 ;
     RECT  55.728 18.221 56.754 18.563 ;
     RECT  15.915 12.659 16.197 18.565 ;
     RECT  15.915 18.565 16.29 18.605 ;
     RECT  5.115 18.329 5.397 18.661 ;
     RECT  23.328 18.031 24.297 18.661 ;
     RECT  14.832 18.283 14.85 18.667 ;
     RECT  60.372 18.317 62.334 18.689 ;
     RECT  60.372 18.689 60.642 18.725 ;
     RECT  0.036 17.837 0.846 18.733 ;
     RECT  22.824 18.661 24.462 18.761 ;
     RECT  63.864 18.221 63.954 18.763 ;
     RECT  14.832 18.667 14.958 18.797 ;
     RECT  21.315 18.427 21.798 18.797 ;
     RECT  25.776 18.461 25.794 18.797 ;
     RECT  54.72 18.419 54.81 18.797 ;
     RECT  28.62 18.023 35.097 18.841 ;
     RECT  63.864 18.763 63.99 18.859 ;
     RECT  47.34 18.811 47.358 18.955 ;
     RECT  57.708 18.185 59.634 18.955 ;
     RECT  60.372 18.725 60.57 18.955 ;
     RECT  63.864 18.859 64.026 18.955 ;
     RECT  28.62 18.841 35.622 18.959 ;
     RECT  47.34 18.955 47.394 18.967 ;
     RECT  55.908 18.563 56.754 18.989 ;
     RECT  28.62 18.959 35.097 18.995 ;
     RECT  56.088 18.989 56.754 19.031 ;
     RECT  63.828 18.955 64.026 19.031 ;
     RECT  61.815 18.689 62.334 19.039 ;
     RECT  38.736 18.967 38.754 19.067 ;
     RECT  46.764 18.967 47.394 19.067 ;
     RECT  22.824 18.761 24.297 19.085 ;
     RECT  26.715 17.933 26.997 19.111 ;
     RECT  56.376 19.031 56.754 19.111 ;
     RECT  57.708 18.955 60.57 19.111 ;
     RECT  21.315 18.797 21.69 19.133 ;
     RECT  22.824 19.085 22.842 19.133 ;
     RECT  5.115 18.661 5.49 19.139 ;
     RECT  47.376 19.067 47.394 19.229 ;
     RECT  56.376 19.111 60.57 19.229 ;
     RECT  26.1 19.111 26.997 19.265 ;
     RECT  63.864 19.031 64.026 19.265 ;
     RECT  35.82 19.075 35.838 19.337 ;
     RECT  56.415 19.229 57.438 19.337 ;
     RECT  58.788 19.229 60.57 19.337 ;
     RECT  63.864 19.265 63.882 19.337 ;
     RECT  54.72 18.797 54.738 19.373 ;
     RECT  59.115 19.337 60.57 19.373 ;
     RECT  61.815 19.039 62.694 19.373 ;
     RECT  56.415 19.337 57.33 19.409 ;
     RECT  4.356 18.329 4.374 19.471 ;
     RECT  5.115 19.139 5.397 19.471 ;
     RECT  13.215 18.329 13.497 19.471 ;
     RECT  21.315 19.133 21.597 19.471 ;
     RECT  7.56 18.461 8.097 19.483 ;
     RECT  60.552 19.373 60.57 19.571 ;
     RECT  26.208 19.265 26.997 19.613 ;
     RECT  0.036 18.733 1.134 19.949 ;
     RECT  14.832 18.797 14.85 20.011 ;
     RECT  10.515 17.453 10.797 20.107 ;
     RECT  28.764 18.995 35.097 20.111 ;
     RECT  14.832 20.011 14.958 20.141 ;
     RECT  26.64 19.613 26.997 20.141 ;
     RECT  10.515 20.107 10.818 20.183 ;
     RECT  22.824 20.107 22.842 20.191 ;
     RECT  24.015 19.085 24.297 20.191 ;
     RECT  6.84 19.483 8.097 20.333 ;
     RECT  14.832 20.141 14.922 20.333 ;
     RECT  22.824 20.191 24.297 20.333 ;
     RECT  22.896 20.333 24.297 20.429 ;
     RECT  6.912 20.333 8.097 20.477 ;
     RECT  14.904 20.333 14.922 20.477 ;
     RECT  22.896 20.429 22.914 20.477 ;
     RECT  13.104 19.471 13.497 20.489 ;
     RECT  21.204 19.471 21.597 20.489 ;
     RECT  1.98 12.047 3.402 20.615 ;
     RECT  1.98 20.615 3.33 20.717 ;
     RECT  2.412 20.717 3.33 20.849 ;
     RECT  28.764 20.111 33.93 20.849 ;
     RECT  4.356 19.471 5.397 20.885 ;
     RECT  4.464 20.885 5.397 21.029 ;
     RECT  7.56 20.477 8.097 21.155 ;
     RECT  21.315 20.489 21.597 21.163 ;
     RECT  5.004 21.029 5.397 21.259 ;
     RECT  28.764 20.849 32.706 21.263 ;
     RECT  21.315 21.163 21.69 21.293 ;
     RECT  5.004 21.259 5.49 21.299 ;
     RECT  28.764 21.263 31.374 21.389 ;
     RECT  2.415 20.849 3.33 21.425 ;
     RECT  33.804 20.849 33.93 21.425 ;
     RECT  0.036 19.949 0.846 21.433 ;
     RECT  33.804 21.425 33.822 21.569 ;
     RECT  2.415 21.425 3.258 21.631 ;
     RECT  13.215 20.489 13.497 21.631 ;
     RECT  21.315 21.293 21.597 21.631 ;
     RECT  26.715 20.141 26.997 21.631 ;
     RECT  0.036 21.433 1.134 21.659 ;
     RECT  2.304 21.631 3.258 21.677 ;
     RECT  5.004 21.299 5.397 21.677 ;
     RECT  13.104 21.631 13.497 21.677 ;
     RECT  21.204 21.631 21.597 21.677 ;
     RECT  45.615 14.237 45.897 21.691 ;
     RECT  28.764 21.389 31.05 21.725 ;
     RECT  6.948 21.643 6.966 21.739 ;
     RECT  10.515 20.183 10.797 21.739 ;
     RECT  6.84 21.739 6.966 21.773 ;
     RECT  26.604 21.631 26.997 21.773 ;
     RECT  32.115 21.263 32.706 21.773 ;
     RECT  45.288 21.691 45.897 21.787 ;
     RECT  10.515 21.739 10.818 21.803 ;
     RECT  14.832 21.163 14.85 21.821 ;
     RECT  45.288 21.787 46.278 21.929 ;
     RECT  18.615 18.464 19.53 21.965 ;
     RECT  6.84 21.773 6.858 22.013 ;
     RECT  22.824 21.163 22.842 22.013 ;
     RECT  0.072 21.659 1.134 22.061 ;
     RECT  15.915 18.605 16.197 22.081 ;
     RECT  0.072 22.061 0.846 22.157 ;
     RECT  15.915 22.081 16.506 22.253 ;
     RECT  28.764 21.725 29.97 22.301 ;
     RECT  30.888 21.725 31.05 22.349 ;
     RECT  0.072 22.157 0.378 22.505 ;
     RECT  2.415 21.677 3.258 22.603 ;
     RECT  2.304 22.603 3.258 22.649 ;
     RECT  2.415 22.649 3.258 22.877 ;
     RECT  0.108 22.505 0.378 23.117 ;
     RECT  0.324 23.117 0.378 23.213 ;
     RECT  0.36 23.213 0.378 23.309 ;
     RECT  30.888 22.349 30.906 27.059 ;
     RECT  30.924 27.355 30.942 27.481 ;
     RECT  32.115 21.773 32.397 27.481 ;
     RECT  29.415 22.301 29.97 27.509 ;
     RECT  2.415 22.877 2.697 27.557 ;
     RECT  5.115 21.677 5.397 27.557 ;
     RECT  7.815 21.155 8.097 27.557 ;
     RECT  10.515 21.803 10.797 27.557 ;
     RECT  13.215 21.677 13.497 27.557 ;
     RECT  15.915 22.253 16.197 27.557 ;
     RECT  18.615 21.965 18.897 27.557 ;
     RECT  21.315 21.677 21.597 27.557 ;
     RECT  24.015 20.429 24.297 27.557 ;
     RECT  26.715 21.773 26.997 27.557 ;
     RECT  29.415 27.509 29.697 27.557 ;
     RECT  34.815 20.111 35.097 27.557 ;
     RECT  37.515 15.755 37.797 27.557 ;
     RECT  40.215 2.413 40.497 27.557 ;
     RECT  42.915 2.413 43.197 27.557 ;
     RECT  45.615 21.929 45.897 27.557 ;
     RECT  48.315 17.339 48.597 27.557 ;
     RECT  51.015 18.221 51.297 27.557 ;
     RECT  53.715 16.979 53.997 27.557 ;
     RECT  56.415 19.409 56.697 27.557 ;
     RECT  59.115 19.373 59.397 27.557 ;
     RECT  61.815 19.373 62.097 27.557 ;
     RECT  30.924 27.481 32.397 27.599 ;
     RECT  31.176 27.599 31.518 27.671 ;
     RECT  2.607 27.557 2.697 27.827 ;
     RECT  5.307 27.557 5.397 27.827 ;
     RECT  8.007 27.557 8.097 27.827 ;
     RECT  10.707 27.557 10.797 27.827 ;
     RECT  13.407 27.557 13.497 27.827 ;
     RECT  16.107 27.557 16.197 27.827 ;
     RECT  18.807 27.557 18.897 27.827 ;
     RECT  21.507 27.557 21.597 27.827 ;
     RECT  24.207 27.557 24.297 27.827 ;
     RECT  26.907 27.557 26.997 27.827 ;
     RECT  29.607 27.557 29.697 27.827 ;
     RECT  32.307 27.599 32.397 27.827 ;
     RECT  35.007 27.557 35.097 27.827 ;
     RECT  37.707 27.557 37.797 27.827 ;
     RECT  40.407 27.557 40.497 27.827 ;
     RECT  43.107 27.557 43.197 27.827 ;
     RECT  45.807 27.557 45.897 27.827 ;
     RECT  48.507 27.557 48.597 27.827 ;
     RECT  51.207 27.557 51.297 27.827 ;
     RECT  53.907 27.557 53.997 27.827 ;
     RECT  56.607 27.557 56.697 27.827 ;
     RECT  59.307 27.557 59.397 27.827 ;
     RECT  62.007 27.557 62.097 27.827 ;
     RECT  31.428 27.671 31.518 27.917 ;
     RECT  31.5 27.917 31.518 29.659 ;
     RECT  31.428 29.659 31.518 29.995 ;
     RECT  31.284 29.995 31.518 30.035 ;
     RECT  31.356 30.035 31.518 30.204 ;
    LAYER M4 ;
     RECT  0.06 10.992 0.097 23.304 ;
     RECT  0.097 10.896 0.209 23.304 ;
     RECT  0.209 10.992 0.389 23.304 ;
     RECT  0.389 10.992 2.408 22.872 ;
     RECT  2.408 2.148 2.512 27.552 ;
     RECT  2.512 2.418 2.6 27.552 ;
     RECT  2.6 2.418 2.704 27.822 ;
     RECT  2.704 10.992 2.765 22.872 ;
     RECT  2.765 11.136 3.269 22.872 ;
     RECT  3.269 11.136 5.108 22.344 ;
     RECT  5.108 2.148 5.212 27.552 ;
     RECT  5.212 2.418 5.3 27.552 ;
     RECT  5.3 2.418 5.404 27.822 ;
     RECT  5.404 11.136 7.808 22.344 ;
     RECT  7.808 2.148 7.912 27.552 ;
     RECT  7.912 2.418 8 27.552 ;
     RECT  8 2.418 8.104 27.822 ;
     RECT  8.104 11.136 10.508 22.344 ;
     RECT  10.508 2.148 10.612 27.552 ;
     RECT  10.612 2.418 10.7 27.552 ;
     RECT  10.7 2.418 10.804 27.822 ;
     RECT  10.804 11.136 13.208 22.344 ;
     RECT  13.208 2.148 13.312 27.552 ;
     RECT  13.312 2.418 13.4 27.552 ;
     RECT  13.4 2.418 13.504 27.822 ;
     RECT  13.504 11.136 15.908 22.344 ;
     RECT  15.908 2.148 16.012 27.552 ;
     RECT  16.012 2.418 16.1 27.552 ;
     RECT  16.1 2.418 16.204 27.822 ;
     RECT  16.204 11.136 18.608 22.344 ;
     RECT  18.608 2.148 18.712 27.552 ;
     RECT  18.712 2.418 18.8 27.552 ;
     RECT  18.8 2.418 18.904 27.822 ;
     RECT  18.904 11.136 21.308 22.344 ;
     RECT  21.308 2.148 21.412 27.552 ;
     RECT  21.412 2.418 21.5 27.552 ;
     RECT  21.5 2.418 21.604 27.822 ;
     RECT  21.604 11.136 24.008 22.344 ;
     RECT  24.008 2.148 24.112 27.552 ;
     RECT  24.112 2.418 24.2 27.552 ;
     RECT  24.2 2.418 24.304 27.822 ;
     RECT  24.304 11.136 26.708 22.344 ;
     RECT  26.708 2.148 26.812 27.552 ;
     RECT  26.812 2.418 26.9 27.552 ;
     RECT  26.9 2.418 27.004 27.822 ;
     RECT  27.004 11.136 29.408 22.344 ;
     RECT  29.408 2.148 29.512 27.552 ;
     RECT  29.512 2.418 29.6 27.552 ;
     RECT  29.6 2.418 29.704 27.822 ;
     RECT  29.704 11.136 30.773 22.344 ;
     RECT  30.773 11.136 30.803 17.736 ;
     RECT  30.803 11.136 30.881 17.64 ;
     RECT  30.913 27.36 30.997 27.384 ;
     RECT  30.773 21.504 31.061 22.344 ;
     RECT  31.273 30 31.417 30.024 ;
     RECT  31.417 29.664 31.427 30.024 ;
     RECT  31.417 27.888 31.523 27.912 ;
     RECT  31.427 29.664 31.523 29.688 ;
     RECT  30.881 11.136 32.108 15.24 ;
     RECT  30.881 16.512 32.108 17.64 ;
     RECT  30.773 18.768 32.108 19.896 ;
     RECT  31.061 21.504 32.108 21.768 ;
     RECT  32.108 2.148 32.212 27.822 ;
     RECT  32.212 2.418 32.404 27.822 ;
     RECT  32.404 18.768 32.573 19.896 ;
     RECT  32.404 21.504 32.717 21.768 ;
     RECT  32.404 16.368 32.897 17.64 ;
     RECT  32.573 18.768 32.969 19.656 ;
     RECT  32.404 11.136 33.113 14.184 ;
     RECT  32.969 18.96 33.365 19.656 ;
     RECT  32.717 21.504 33.833 21.528 ;
     RECT  32.897 16.368 34.261 16.392 ;
     RECT  32.897 17.424 34.261 17.64 ;
     RECT  33.113 11.232 34.808 14.184 ;
     RECT  32.404 15.216 34.808 15.24 ;
     RECT  34.261 16.368 34.808 17.64 ;
     RECT  33.365 18.96 34.808 19.56 ;
     RECT  34.808 2.148 34.912 27.552 ;
     RECT  34.912 2.418 35 27.552 ;
     RECT  35 2.418 35.104 27.822 ;
     RECT  35.104 16.56 35.309 17.64 ;
     RECT  35.104 11.712 36.425 14.184 ;
     RECT  36.425 11.712 37.508 12.888 ;
     RECT  36.425 14.16 37.508 14.184 ;
     RECT  35.309 17.424 37.508 17.64 ;
     RECT  35.104 18.96 37.508 18.984 ;
     RECT  37.508 2.148 37.612 27.552 ;
     RECT  37.612 2.418 37.7 27.552 ;
     RECT  37.7 2.418 37.804 27.822 ;
     RECT  37.804 17.328 38.801 17.64 ;
     RECT  37.804 11.712 40.208 12.888 ;
     RECT  37.804 14.16 40.208 14.184 ;
     RECT  38.801 17.424 40.208 17.64 ;
     RECT  37.804 18.96 40.208 18.984 ;
     RECT  40.208 2.148 40.312 27.552 ;
     RECT  40.312 2.418 40.4 27.552 ;
     RECT  40.4 2.418 40.504 27.822 ;
     RECT  40.504 11.712 42.908 12.888 ;
     RECT  40.504 14.16 42.908 14.184 ;
     RECT  40.504 17.424 42.908 17.64 ;
     RECT  40.504 18.96 42.908 18.984 ;
     RECT  42.908 2.148 43.012 27.552 ;
     RECT  43.012 2.418 43.1 27.552 ;
     RECT  43.1 2.418 43.204 27.822 ;
     RECT  43.204 17.424 45.013 17.64 ;
     RECT  43.204 11.712 45.157 13.08 ;
     RECT  43.204 14.16 45.157 14.184 ;
     RECT  45.157 11.712 45.608 14.184 ;
     RECT  45.013 16.896 45.608 17.64 ;
     RECT  43.204 18.96 45.608 18.984 ;
     RECT  45.277 21.696 45.608 21.72 ;
     RECT  45.608 2.148 45.712 27.552 ;
     RECT  45.712 2.418 45.8 27.552 ;
     RECT  45.8 2.418 45.904 27.822 ;
     RECT  45.904 16.368 46.307 17.64 ;
     RECT  45.904 21.696 46.333 21.816 ;
     RECT  46.333 21.696 46.451 21.72 ;
     RECT  45.904 11.712 46.477 14.232 ;
     RECT  45.904 18.96 47.329 18.984 ;
     RECT  46.477 11.712 48.308 13.848 ;
     RECT  46.307 16.368 48.308 16.92 ;
     RECT  47.329 18.816 48.308 18.984 ;
     RECT  48.308 2.148 48.412 27.552 ;
     RECT  48.412 2.418 48.5 27.552 ;
     RECT  48.5 2.418 48.604 27.822 ;
     RECT  48.604 16.368 50.713 16.872 ;
     RECT  48.604 11.712 51.008 13.848 ;
     RECT  50.713 16.368 51.008 17.784 ;
     RECT  48.604 18.96 51.008 18.984 ;
     RECT  51.008 2.148 51.112 27.552 ;
     RECT  51.112 2.418 51.2 27.552 ;
     RECT  51.2 2.418 51.304 27.822 ;
     RECT  51.304 11.712 53.017 13.848 ;
     RECT  53.017 11.712 53.708 14.184 ;
     RECT  51.304 16.368 53.708 16.872 ;
     RECT  51.304 18.96 53.708 18.984 ;
     RECT  53.708 2.148 53.812 27.552 ;
     RECT  53.812 2.418 53.9 27.552 ;
     RECT  53.9 2.418 54.004 27.822 ;
     RECT  54.004 10.464 55.177 10.488 ;
     RECT  55.177 10.272 55.321 10.488 ;
     RECT  54.004 16.368 55.381 16.872 ;
     RECT  55.321 10.272 55.429 10.584 ;
     RECT  54.004 11.712 55.429 13.848 ;
     RECT  54.004 6.864 55.669 6.888 ;
     RECT  54.004 18.96 55.897 18.984 ;
     RECT  55.897 18.816 56.005 18.984 ;
     RECT  55.381 15.888 56.221 16.872 ;
     RECT  55.429 9.504 56.293 13.848 ;
     RECT  56.293 9.504 56.365 14.28 ;
     RECT  56.221 15.552 56.365 16.872 ;
     RECT  55.669 6.864 56.408 7.416 ;
     RECT  56.365 9.504 56.408 16.872 ;
     RECT  56.005 17.904 56.408 18.984 ;
     RECT  56.408 2.148 56.512 27.552 ;
     RECT  56.512 2.418 56.6 27.552 ;
     RECT  56.6 2.418 56.704 27.822 ;
     RECT  56.704 7.104 56.981 8.424 ;
     RECT  56.704 9.504 57.697 18.024 ;
     RECT  56.981 8.4 57.733 8.424 ;
     RECT  57.697 9.504 57.733 18.6 ;
     RECT  57.733 8.4 57.953 18.6 ;
     RECT  56.981 7.104 58.813 7.128 ;
     RECT  58.813 7.104 58.981 7.992 ;
     RECT  57.953 9.072 58.981 18.6 ;
     RECT  58.981 7.104 59.108 18.6 ;
     RECT  59.108 2.148 59.212 27.552 ;
     RECT  59.212 2.418 59.3 27.552 ;
     RECT  59.3 2.418 59.404 27.822 ;
     RECT  59.404 7.104 60.185 18.984 ;
     RECT  60.185 7.104 60.401 18.264 ;
     RECT  60.401 7.104 60.545 13.704 ;
     RECT  60.545 8.544 60.581 13.704 ;
     RECT  60.545 7.104 60.689 7.176 ;
     RECT  60.689 7.152 61.808 7.176 ;
     RECT  60.581 9.36 61.808 13.704 ;
     RECT  60.401 14.688 61.808 18.264 ;
     RECT  61.808 2.148 61.912 27.552 ;
     RECT  61.912 2.418 62 27.552 ;
     RECT  62 2.418 62.104 27.822 ;
     RECT  62.104 6.96 63.241 10.344 ;
     RECT  63.241 6.864 63.277 10.344 ;
     RECT  62.104 11.376 63.277 19.08 ;
     RECT  63.277 6.864 64.716 19.08 ;
    LAYER M5 ;
     RECT  2.4 2.137 2.52 2.151 ;
     RECT  5.1 2.137 5.22 2.151 ;
     RECT  7.8 2.137 7.92 2.151 ;
     RECT  10.5 2.137 10.62 2.151 ;
     RECT  13.2 2.137 13.32 2.151 ;
     RECT  15.9 2.137 16.02 2.151 ;
     RECT  18.6 2.137 18.72 2.151 ;
     RECT  21.3 2.137 21.42 2.151 ;
     RECT  24 2.137 24.12 2.151 ;
     RECT  26.7 2.137 26.82 2.151 ;
     RECT  29.4 2.137 29.52 2.151 ;
     RECT  32.1 2.137 32.22 2.151 ;
     RECT  34.8 2.137 34.92 2.151 ;
     RECT  37.5 2.137 37.62 2.151 ;
     RECT  40.2 2.137 40.32 2.151 ;
     RECT  42.9 2.137 43.02 2.151 ;
     RECT  45.6 2.137 45.72 2.151 ;
     RECT  48.3 2.137 48.42 2.151 ;
     RECT  51 2.137 51.12 2.151 ;
     RECT  53.7 2.137 53.82 2.151 ;
     RECT  56.4 2.137 56.52 2.151 ;
     RECT  59.1 2.137 59.22 2.151 ;
     RECT  61.8 2.137 61.92 2.151 ;
     RECT  56.4 2.151 56.712 7.381 ;
     RECT  55.68 7.381 56.712 7.957 ;
     RECT  59.1 2.151 59.412 7.957 ;
     RECT  58.992 7.957 59.412 9.061 ;
     RECT  58.128 9.061 59.412 9.445 ;
     RECT  58.128 9.445 59.832 9.541 ;
     RECT  57.984 9.541 59.832 9.637 ;
     RECT  57.888 9.637 59.832 10.069 ;
     RECT  55.68 7.957 56.808 10.165 ;
     RECT  57.888 10.069 60.024 10.165 ;
     RECT  55.68 10.165 60.024 10.261 ;
     RECT  55.584 10.261 60.024 10.307 ;
     RECT  58.992 10.307 60.024 10.835 ;
     RECT  24 2.151 24.312 11.221 ;
     RECT  23.904 11.221 24.312 11.411 ;
     RECT  58.992 10.835 59.412 11.459 ;
     RECT  2.4 2.151 2.712 11.557 ;
     RECT  55.584 10.307 58.008 12.515 ;
     RECT  55.68 12.515 58.008 12.707 ;
     RECT  2.4 11.557 3.288 12.803 ;
     RECT  14.832 12.565 14.856 12.803 ;
     RECT  22.8 12.565 22.824 12.803 ;
     RECT  56.304 12.707 58.008 12.803 ;
     RECT  53.7 2.151 54.012 12.853 ;
     RECT  45.6 2.151 45.912 13.045 ;
     RECT  53.7 12.853 54.696 13.091 ;
     RECT  56.304 12.803 57.912 13.139 ;
     RECT  24 11.411 24.312 13.525 ;
     RECT  59.1 11.459 59.412 13.621 ;
     RECT  23.904 13.525 24.312 13.667 ;
     RECT  45.168 13.045 46.44 13.811 ;
     RECT  59.1 13.621 60.216 14.099 ;
     RECT  32.1 2.151 32.412 14.149 ;
     RECT  56.304 13.139 56.712 14.291 ;
     RECT  56.4 14.291 56.712 14.581 ;
     RECT  57.888 13.139 57.912 14.581 ;
     RECT  56.4 14.581 57.912 14.627 ;
     RECT  22.8 14.101 22.824 14.675 ;
     RECT  59.1 14.099 60.12 15.973 ;
     RECT  56.4 14.627 57.528 16.019 ;
     RECT  59.1 15.973 60.408 16.019 ;
     RECT  55.392 15.877 55.416 16.883 ;
     RECT  45.216 13.811 46.44 16.885 ;
     RECT  48.3 2.151 48.612 16.885 ;
     RECT  60.384 16.019 60.408 17.029 ;
     RECT  61.8 2.151 62.112 17.029 ;
     RECT  22.8 17.077 22.824 17.459 ;
     RECT  45.024 16.885 48.612 17.459 ;
     RECT  31.392 14.149 32.412 17.605 ;
     RECT  30.768 17.605 32.412 17.747 ;
     RECT  57.792 17.029 57.816 17.987 ;
     RECT  60.384 17.029 62.112 17.987 ;
     RECT  61.008 17.987 62.112 18.275 ;
     RECT  24 13.667 24.312 18.277 ;
     RECT  23.904 18.277 24.312 18.467 ;
     RECT  26.7 2.151 27.012 18.661 ;
     RECT  25.872 18.661 27.012 18.803 ;
     RECT  45.6 17.459 48.612 18.851 ;
     RECT  31.392 17.747 32.412 18.949 ;
     RECT  24 18.467 24.312 19.477 ;
     RECT  23.904 19.477 24.312 20.147 ;
     RECT  24 20.147 24.312 21.637 ;
     RECT  45.6 18.851 46.44 21.731 ;
     RECT  23.904 21.637 24.312 21.779 ;
     RECT  45.6 21.731 46.296 21.827 ;
     RECT  30.96 18.949 32.412 27.395 ;
     RECT  2.4 12.803 2.712 27.819 ;
     RECT  5.1 2.151 5.412 27.819 ;
     RECT  7.8 2.151 8.112 27.819 ;
     RECT  10.5 2.151 10.812 27.819 ;
     RECT  13.2 2.151 13.512 27.819 ;
     RECT  15.9 2.151 16.212 27.819 ;
     RECT  18.6 2.151 18.912 27.819 ;
     RECT  21.3 2.151 21.612 27.819 ;
     RECT  24 21.779 24.312 27.819 ;
     RECT  26.7 18.803 27.012 27.819 ;
     RECT  29.4 2.151 29.712 27.819 ;
     RECT  34.8 2.151 35.112 27.819 ;
     RECT  37.5 2.151 37.812 27.819 ;
     RECT  40.2 2.151 40.512 27.819 ;
     RECT  42.9 2.151 43.212 27.819 ;
     RECT  45.6 21.827 45.912 27.819 ;
     RECT  48.3 18.851 48.612 27.819 ;
     RECT  51 2.151 51.312 27.819 ;
     RECT  53.7 13.091 54.012 27.819 ;
     RECT  56.4 16.019 56.712 27.819 ;
     RECT  59.1 16.019 59.412 27.819 ;
     RECT  61.8 18.275 62.112 27.819 ;
     RECT  2.592 27.819 2.712 27.833 ;
     RECT  5.292 27.819 5.412 27.833 ;
     RECT  7.992 27.819 8.112 27.833 ;
     RECT  10.692 27.819 10.812 27.833 ;
     RECT  13.392 27.819 13.512 27.833 ;
     RECT  16.092 27.819 16.212 27.833 ;
     RECT  18.792 27.819 18.912 27.833 ;
     RECT  21.492 27.819 21.612 27.833 ;
     RECT  24.192 27.819 24.312 27.833 ;
     RECT  26.892 27.819 27.012 27.833 ;
     RECT  29.592 27.819 29.712 27.833 ;
     RECT  31.392 27.395 32.412 27.833 ;
     RECT  34.992 27.819 35.112 27.833 ;
     RECT  37.692 27.819 37.812 27.833 ;
     RECT  40.392 27.819 40.512 27.833 ;
     RECT  43.092 27.819 43.212 27.833 ;
     RECT  45.792 27.819 45.912 27.833 ;
     RECT  48.492 27.819 48.612 27.833 ;
     RECT  51.192 27.819 51.312 27.833 ;
     RECT  53.892 27.819 54.012 27.833 ;
     RECT  56.592 27.819 56.712 27.833 ;
     RECT  59.292 27.819 59.412 27.833 ;
     RECT  61.992 27.819 62.112 27.833 ;
     RECT  31.392 27.833 31.512 29.699 ;
     RECT  31.392 29.699 31.416 30.035 ;
  END
END qfd_rlyh0_128_EW_65x30
END LIBRARY
